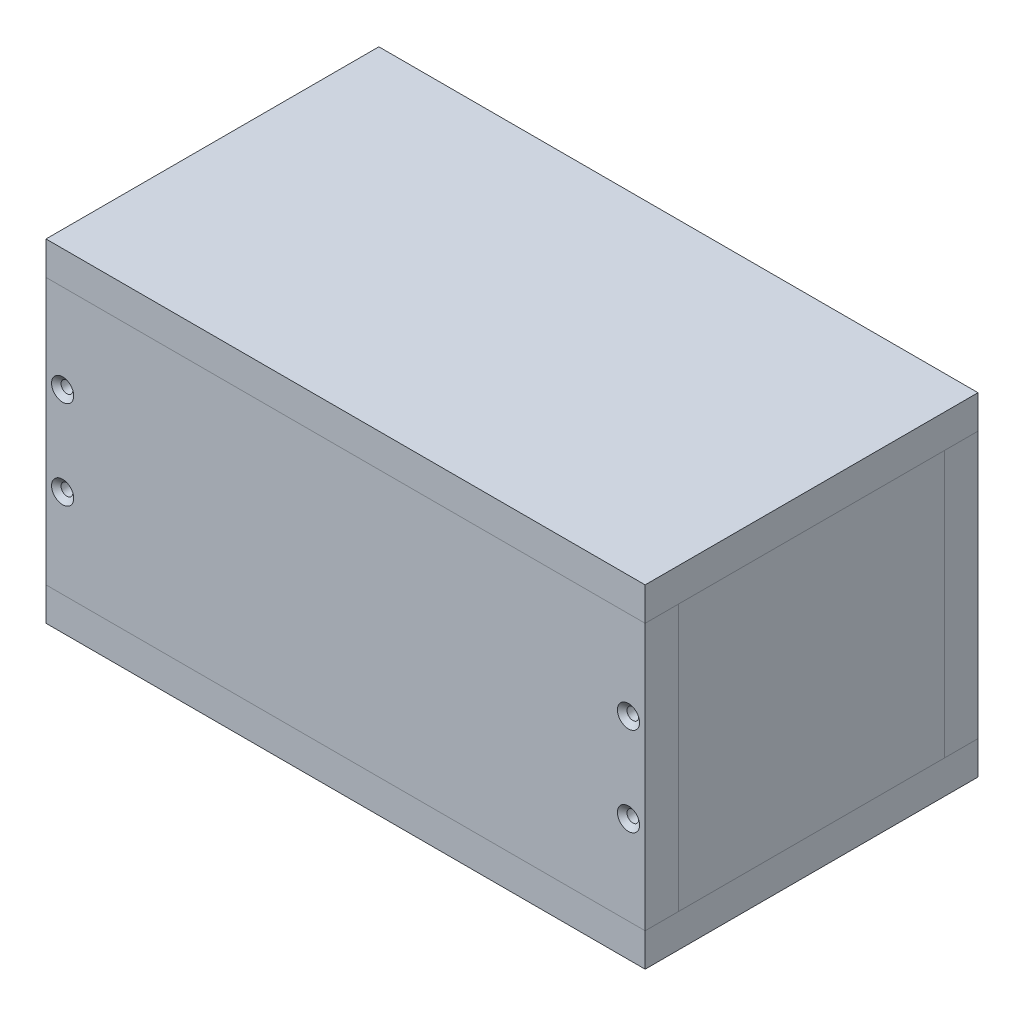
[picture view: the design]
ISO-10303-21;
HEADER;
FILE_DESCRIPTION(('STEP AP214'),'2;1');
FILE_NAME('part.step','',(''),(''),'','','');
FILE_SCHEMA(('AUTOMOTIVE_DESIGN { 1 0 10303 214 1 1 1 1 }'));
ENDSEC;
DATA;
#1=APPLICATION_CONTEXT('core data for automotive mechanical design processes');
#2=APPLICATION_PROTOCOL_DEFINITION('international standard','automotive_design',2000,#1);
#3=PRODUCT_CONTEXT('',#1,'mechanical');
#4=PRODUCT('Part','Part','',(#3));
#5=PRODUCT_RELATED_PRODUCT_CATEGORY('part','',(#4));
#6=PRODUCT_DEFINITION_FORMATION('','',#4);
#7=PRODUCT_DEFINITION_CONTEXT('part definition',#1,'design');
#8=PRODUCT_DEFINITION('design','',#6,#7);
#9=PRODUCT_DEFINITION_SHAPE('','',#8);
#10=(LENGTH_UNIT() NAMED_UNIT(*) SI_UNIT(.MILLI.,.METRE.));
#11=(NAMED_UNIT(*) PLANE_ANGLE_UNIT() SI_UNIT($,.RADIAN.));
#12=(NAMED_UNIT(*) SI_UNIT($,.STERADIAN.) SOLID_ANGLE_UNIT());
#13=UNCERTAINTY_MEASURE_WITH_UNIT(LENGTH_MEASURE(1.E-05),#10,'distance_accuracy_value','');
#14=(GEOMETRIC_REPRESENTATION_CONTEXT(3) GLOBAL_UNCERTAINTY_ASSIGNED_CONTEXT((#13)) GLOBAL_UNIT_ASSIGNED_CONTEXT((#10,
#11,#12)) REPRESENTATION_CONTEXT('',''));
#15=CARTESIAN_POINT('',(0.,0.,0.));
#16=DIRECTION('',(0.,0.,1.));
#17=DIRECTION('',(1.,0.,0.));
#18=AXIS2_PLACEMENT_3D('',#15,#16,#17);
#19=CARTESIAN_POINT('',(114.3,114.3,63.5));
#20=DIRECTION('',(-1.,0.,0.));
#21=DIRECTION('',(0.,0.,1.));
#22=AXIS2_PLACEMENT_3D('',#19,#20,#21);
#23=PLANE('',#22);
#24=DIRECTION('',(0.,0.,-1.));
#25=VECTOR('',#24,1.);
#26=CARTESIAN_POINT('',(114.3,101.6,63.5));
#27=LINE('',#26,#25);
#28=CARTESIAN_POINT('',(114.3,101.6,63.5));
#29=VERTEX_POINT('',#28);
#30=CARTESIAN_POINT('',(114.3,101.6,-63.5));
#31=VERTEX_POINT('',#30);
#32=EDGE_CURVE('E108',#29,#31,#27,.T.);
#33=ORIENTED_EDGE('',*,*,#32,.T.);
#34=DIRECTION('',(0.,-1.,0.));
#35=VECTOR('',#34,1.);
#36=CARTESIAN_POINT('',(114.3,114.3,-63.5));
#37=LINE('',#36,#35);
#38=CARTESIAN_POINT('',(114.3,114.3,-63.5));
#39=VERTEX_POINT('',#38);
#40=EDGE_CURVE('E12',#39,#31,#37,.T.);
#41=ORIENTED_EDGE('',*,*,#40,.F.);
#42=DIRECTION('',(0.,0.,-1.));
#43=VECTOR('',#42,1.);
#44=CARTESIAN_POINT('',(114.3,114.3,63.5));
#45=LINE('',#44,#43);
#46=CARTESIAN_POINT('',(114.3,114.3,63.5));
#47=VERTEX_POINT('',#46);
#48=EDGE_CURVE('E96',#47,#39,#45,.T.);
#49=ORIENTED_EDGE('',*,*,#48,.F.);
#50=DIRECTION('',(0.,-1.,0.));
#51=VECTOR('',#50,1.);
#52=CARTESIAN_POINT('',(114.3,114.3,63.5));
#53=LINE('',#52,#51);
#54=EDGE_CURVE('E104',#47,#29,#53,.T.);
#55=ORIENTED_EDGE('',*,*,#54,.T.);
#56=EDGE_LOOP('',(#33,#41,#49,#55));
#57=FACE_BOUND('',#56,.T.);
#58=ADVANCED_FACE('F45',(#57),#23,.F.);
#59=CARTESIAN_POINT('',(114.3,114.3,-63.5));
#60=DIRECTION('',(0.,0.,1.));
#61=DIRECTION('',(1.,0.,0.));
#62=AXIS2_PLACEMENT_3D('',#59,#60,#61);
#63=PLANE('',#62);
#64=DIRECTION('',(-1.,0.,0.));
#65=VECTOR('',#64,1.);
#66=CARTESIAN_POINT('',(114.3,101.6,-63.5));
#67=LINE('',#66,#65);
#68=CARTESIAN_POINT('',(-114.3,101.6,-63.5));
#69=VERTEX_POINT('',#68);
#70=EDGE_CURVE('E100',#31,#69,#67,.T.);
#71=ORIENTED_EDGE('',*,*,#70,.T.);
#72=DIRECTION('',(0.,-1.,0.));
#73=VECTOR('',#72,1.);
#74=CARTESIAN_POINT('',(-114.3,114.3,-63.5));
#75=LINE('',#74,#73);
#76=CARTESIAN_POINT('',(-114.3,114.3,-63.5));
#77=VERTEX_POINT('',#76);
#78=EDGE_CURVE('E53',#77,#69,#75,.T.);
#79=ORIENTED_EDGE('',*,*,#78,.F.);
#80=DIRECTION('',(-1.,0.,0.));
#81=VECTOR('',#80,1.);
#82=CARTESIAN_POINT('',(114.3,114.3,-63.5));
#83=LINE('',#82,#81);
#84=EDGE_CURVE('E91',#39,#77,#83,.T.);
#85=ORIENTED_EDGE('',*,*,#84,.F.);
#86=ORIENTED_EDGE('',*,*,#40,.T.);
#87=EDGE_LOOP('',(#71,#79,#85,#86));
#88=FACE_BOUND('',#87,.T.);
#89=ADVANCED_FACE('F99',(#88),#63,.F.);
#90=CARTESIAN_POINT('',(-114.3,114.3,63.5));
#91=DIRECTION('',(1.,0.,0.));
#92=DIRECTION('',(0.,0.,-1.));
#93=AXIS2_PLACEMENT_3D('',#90,#91,#92);
#94=PLANE('',#93);
#95=DIRECTION('',(0.,0.,1.));
#96=VECTOR('',#95,1.);
#97=CARTESIAN_POINT('',(-114.3,101.6,63.5));
#98=LINE('',#97,#96);
#99=CARTESIAN_POINT('',(-114.3,101.6,63.5));
#100=VERTEX_POINT('',#99);
#101=EDGE_CURVE('E78',#69,#100,#98,.T.);
#102=ORIENTED_EDGE('',*,*,#101,.T.);
#103=DIRECTION('',(0.,-1.,0.));
#104=VECTOR('',#103,1.);
#105=CARTESIAN_POINT('',(-114.3,114.3,63.5));
#106=LINE('',#105,#104);
#107=CARTESIAN_POINT('',(-114.3,114.3,63.5));
#108=VERTEX_POINT('',#107);
#109=EDGE_CURVE('E101',#108,#100,#106,.T.);
#110=ORIENTED_EDGE('',*,*,#109,.F.);
#111=DIRECTION('',(0.,0.,1.));
#112=VECTOR('',#111,1.);
#113=CARTESIAN_POINT('',(-114.3,114.3,63.5));
#114=LINE('',#113,#112);
#115=EDGE_CURVE('E94',#77,#108,#114,.T.);
#116=ORIENTED_EDGE('',*,*,#115,.F.);
#117=ORIENTED_EDGE('',*,*,#78,.T.);
#118=EDGE_LOOP('',(#102,#110,#116,#117));
#119=FACE_BOUND('',#118,.T.);
#120=ADVANCED_FACE('F102',(#119),#94,.F.);
#121=CARTESIAN_POINT('',(114.3,114.3,63.5));
#122=DIRECTION('',(0.,0.,-1.));
#123=DIRECTION('',(-1.,0.,0.));
#124=AXIS2_PLACEMENT_3D('',#121,#122,#123);
#125=PLANE('',#124);
#126=DIRECTION('',(1.,0.,0.));
#127=VECTOR('',#126,1.);
#128=CARTESIAN_POINT('',(114.3,101.6,63.5));
#129=LINE('',#128,#127);
#130=EDGE_CURVE('E84',#100,#29,#129,.T.);
#131=ORIENTED_EDGE('',*,*,#130,.T.);
#132=ORIENTED_EDGE('',*,*,#54,.F.);
#133=DIRECTION('',(1.,0.,0.));
#134=VECTOR('',#133,1.);
#135=CARTESIAN_POINT('',(114.3,114.3,63.5));
#136=LINE('',#135,#134);
#137=EDGE_CURVE('E61',#108,#47,#136,.T.);
#138=ORIENTED_EDGE('',*,*,#137,.F.);
#139=ORIENTED_EDGE('',*,*,#109,.T.);
#140=EDGE_LOOP('',(#131,#132,#138,#139));
#141=FACE_BOUND('',#140,.T.);
#142=ADVANCED_FACE('F115',(#141),#125,.F.);
#143=CARTESIAN_POINT('',(0.,114.3,0.));
#144=DIRECTION('',(0.,1.,0.));
#145=DIRECTION('',(0.,0.,1.));
#146=AXIS2_PLACEMENT_3D('',#143,#144,#145);
#147=PLANE('',#146);
#148=ORIENTED_EDGE('',*,*,#48,.T.);
#149=ORIENTED_EDGE('',*,*,#84,.T.);
#150=ORIENTED_EDGE('',*,*,#115,.T.);
#151=ORIENTED_EDGE('',*,*,#137,.T.);
#152=EDGE_LOOP('',(#148,#149,#150,#151));
#153=FACE_BOUND('',#152,.T.);
#154=ADVANCED_FACE('F92',(#153),#147,.T.);
#155=CARTESIAN_POINT('',(0.,101.6,0.));
#156=DIRECTION('',(0.,1.,0.));
#157=DIRECTION('',(0.,0.,1.));
#158=AXIS2_PLACEMENT_3D('',#155,#156,#157);
#159=PLANE('',#158);
#160=ORIENTED_EDGE('',*,*,#32,.F.);
#161=ORIENTED_EDGE('',*,*,#130,.F.);
#162=ORIENTED_EDGE('',*,*,#101,.F.);
#163=ORIENTED_EDGE('',*,*,#70,.F.);
#164=EDGE_LOOP('',(#160,#161,#162,#163));
#165=FACE_BOUND('',#164,.T.);
#166=ADVANCED_FACE('F118',(#165),#159,.F.);
#167=CLOSED_SHELL('',(#58,#89,#120,#142,#154,#166));
#168=MANIFOLD_SOLID_BREP('B2_NOT_SHOWN',#167);
#169=CARTESIAN_POINT('',(114.3,-12.7,-63.5));
#170=DIRECTION('',(1.,0.,0.));
#171=DIRECTION('',(0.,0.,-1.));
#172=AXIS2_PLACEMENT_3D('',#169,#170,#171);
#173=PLANE('',#172);
#174=DIRECTION('',(0.,0.,-1.));
#175=VECTOR('',#174,1.);
#176=CARTESIAN_POINT('',(114.3,0.,-63.5));
#177=LINE('',#176,#175);
#178=CARTESIAN_POINT('',(114.3,0.,63.4999999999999));
#179=VERTEX_POINT('',#178);
#180=CARTESIAN_POINT('',(114.3,0.,-63.5));
#181=VERTEX_POINT('',#180);
#182=EDGE_CURVE('E245',#179,#181,#177,.T.);
#183=ORIENTED_EDGE('',*,*,#182,.F.);
#184=DIRECTION('',(0.,1.,0.));
#185=VECTOR('',#184,1.);
#186=CARTESIAN_POINT('',(114.3,-12.7,63.4999999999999));
#187=LINE('',#186,#185);
#188=CARTESIAN_POINT('',(114.3,-12.7,63.4999999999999));
#189=VERTEX_POINT('',#188);
#190=EDGE_CURVE('E43',#189,#179,#187,.T.);
#191=ORIENTED_EDGE('',*,*,#190,.F.);
#192=DIRECTION('',(0.,0.,-1.));
#193=VECTOR('',#192,1.);
#194=CARTESIAN_POINT('',(114.3,-12.7,-63.5));
#195=LINE('',#194,#193);
#196=CARTESIAN_POINT('',(114.3,-12.7,-63.5));
#197=VERTEX_POINT('',#196);
#198=EDGE_CURVE('E238',#189,#197,#195,.T.);
#199=ORIENTED_EDGE('',*,*,#198,.T.);
#200=DIRECTION('',(0.,1.,0.));
#201=VECTOR('',#200,1.);
#202=CARTESIAN_POINT('',(114.3,-12.7,-63.5));
#203=LINE('',#202,#201);
#204=EDGE_CURVE('E221',#197,#181,#203,.T.);
#205=ORIENTED_EDGE('',*,*,#204,.T.);
#206=EDGE_LOOP('',(#183,#191,#199,#205));
#207=FACE_BOUND('',#206,.T.);
#208=ADVANCED_FACE('F178',(#207),#173,.T.);
#209=CARTESIAN_POINT('',(114.3,-12.7,63.4999999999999));
#210=DIRECTION('',(0.,0.,1.));
#211=DIRECTION('',(1.,0.,0.));
#212=AXIS2_PLACEMENT_3D('',#209,#210,#211);
#213=PLANE('',#212);
#214=DIRECTION('',(1.,0.,0.));
#215=VECTOR('',#214,1.);
#216=CARTESIAN_POINT('',(114.3,0.,63.4999999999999));
#217=LINE('',#216,#215);
#218=CARTESIAN_POINT('',(-114.3,0.,63.5));
#219=VERTEX_POINT('',#218);
#220=EDGE_CURVE('E240',#219,#179,#217,.T.);
#221=ORIENTED_EDGE('',*,*,#220,.F.);
#222=DIRECTION('',(0.,1.,0.));
#223=VECTOR('',#222,1.);
#224=CARTESIAN_POINT('',(-114.3,-12.7,63.5));
#225=LINE('',#224,#223);
#226=CARTESIAN_POINT('',(-114.3,-12.7,63.5));
#227=VERTEX_POINT('',#226);
#228=EDGE_CURVE('E187',#227,#219,#225,.T.);
#229=ORIENTED_EDGE('',*,*,#228,.F.);
#230=DIRECTION('',(1.,0.,0.));
#231=VECTOR('',#230,1.);
#232=CARTESIAN_POINT('',(114.3,-12.7,63.4999999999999));
#233=LINE('',#232,#231);
#234=EDGE_CURVE('E235',#227,#189,#233,.T.);
#235=ORIENTED_EDGE('',*,*,#234,.T.);
#236=ORIENTED_EDGE('',*,*,#190,.T.);
#237=EDGE_LOOP('',(#221,#229,#235,#236));
#238=FACE_BOUND('',#237,.T.);
#239=ADVANCED_FACE('F310',(#238),#213,.T.);
#240=CARTESIAN_POINT('',(-114.3,-12.7,-63.5));
#241=DIRECTION('',(-1.,0.,0.));
#242=DIRECTION('',(0.,0.,1.));
#243=AXIS2_PLACEMENT_3D('',#240,#241,#242);
#244=PLANE('',#243);
#245=DIRECTION('',(0.,0.,1.));
#246=VECTOR('',#245,1.);
#247=CARTESIAN_POINT('',(-114.3,0.,-63.5));
#248=LINE('',#247,#246);
#249=CARTESIAN_POINT('',(-114.3,0.,-63.5));
#250=VERTEX_POINT('',#249);
#251=EDGE_CURVE('E229',#250,#219,#248,.T.);
#252=ORIENTED_EDGE('',*,*,#251,.F.);
#253=DIRECTION('',(0.,1.,0.));
#254=VECTOR('',#253,1.);
#255=CARTESIAN_POINT('',(-114.3,-12.7,-63.5));
#256=LINE('',#255,#254);
#257=CARTESIAN_POINT('',(-114.3,-12.7,-63.5));
#258=VERTEX_POINT('',#257);
#259=EDGE_CURVE('E224',#258,#250,#256,.T.);
#260=ORIENTED_EDGE('',*,*,#259,.F.);
#261=DIRECTION('',(0.,0.,1.));
#262=VECTOR('',#261,1.);
#263=CARTESIAN_POINT('',(-114.3,-12.7,-63.5));
#264=LINE('',#263,#262);
#265=EDGE_CURVE('E227',#258,#227,#264,.T.);
#266=ORIENTED_EDGE('',*,*,#265,.T.);
#267=ORIENTED_EDGE('',*,*,#228,.T.);
#268=EDGE_LOOP('',(#252,#260,#266,#267));
#269=FACE_BOUND('',#268,.T.);
#270=ADVANCED_FACE('F226',(#269),#244,.T.);
#271=CARTESIAN_POINT('',(114.3,-12.7,-63.5));
#272=DIRECTION('',(0.,0.,-1.));
#273=DIRECTION('',(-1.,0.,0.));
#274=AXIS2_PLACEMENT_3D('',#271,#272,#273);
#275=PLANE('',#274);
#276=DIRECTION('',(-1.,0.,0.));
#277=VECTOR('',#276,1.);
#278=CARTESIAN_POINT('',(114.3,0.,-63.5));
#279=LINE('',#278,#277);
#280=EDGE_CURVE('E248',#181,#250,#279,.T.);
#281=ORIENTED_EDGE('',*,*,#280,.F.);
#282=ORIENTED_EDGE('',*,*,#204,.F.);
#283=DIRECTION('',(-1.,0.,0.));
#284=VECTOR('',#283,1.);
#285=CARTESIAN_POINT('',(114.3,-12.7,-63.5));
#286=LINE('',#285,#284);
#287=EDGE_CURVE('E234',#197,#258,#286,.T.);
#288=ORIENTED_EDGE('',*,*,#287,.T.);
#289=ORIENTED_EDGE('',*,*,#259,.T.);
#290=EDGE_LOOP('',(#281,#282,#288,#289));
#291=FACE_BOUND('',#290,.T.);
#292=ADVANCED_FACE('F237',(#291),#275,.T.);
#293=CARTESIAN_POINT('',(0.,-12.7,0.));
#294=DIRECTION('',(0.,-1.,0.));
#295=DIRECTION('',(0.,0.,-1.));
#296=AXIS2_PLACEMENT_3D('',#293,#294,#295);
#297=PLANE('',#296);
#298=CARTESIAN_POINT('',(57.1500000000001,-12.7,-57.15));
#299=DIRECTION('',(0.,-1.,0.));
#300=DIRECTION('',(0.,0.,-1.));
#301=AXIS2_PLACEMENT_3D('',#298,#299,#300);
#302=CIRCLE('',#301,4.2164);
#303=CARTESIAN_POINT('',(57.1500000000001,-12.7,-61.3664));
#304=VERTEX_POINT('',#303);
#305=EDGE_CURVE('E416',#304,#304,#302,.T.);
#306=ORIENTED_EDGE('',*,*,#305,.F.);
#307=EDGE_LOOP('',(#306));
#308=FACE_BOUND('',#307,.T.);
#309=CARTESIAN_POINT('',(-57.15,-12.7,-57.15));
#310=DIRECTION('',(0.,-1.,0.));
#311=DIRECTION('',(0.,0.,-1.));
#312=AXIS2_PLACEMENT_3D('',#309,#310,#311);
#313=CIRCLE('',#312,4.2164);
#314=CARTESIAN_POINT('',(-57.15,-12.7,-61.3664));
#315=VERTEX_POINT('',#314);
#316=EDGE_CURVE('E272',#315,#315,#313,.T.);
#317=ORIENTED_EDGE('',*,*,#316,.F.);
#318=EDGE_LOOP('',(#317));
#319=FACE_BOUND('',#318,.T.);
#320=CARTESIAN_POINT('',(-57.15,-12.7,57.15));
#321=DIRECTION('',(0.,-1.,0.));
#322=DIRECTION('',(0.,0.,-1.));
#323=AXIS2_PLACEMENT_3D('',#320,#321,#322);
#324=CIRCLE('',#323,4.2164);
#325=CARTESIAN_POINT('',(-57.15,-12.7,52.9336));
#326=VERTEX_POINT('',#325);
#327=EDGE_CURVE('E265',#326,#326,#324,.T.);
#328=ORIENTED_EDGE('',*,*,#327,.F.);
#329=EDGE_LOOP('',(#328));
#330=FACE_BOUND('',#329,.T.);
#331=CARTESIAN_POINT('',(57.1500000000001,-12.7,57.15));
#332=DIRECTION('',(0.,-1.,0.));
#333=DIRECTION('',(0.,0.,-1.));
#334=AXIS2_PLACEMENT_3D('',#331,#332,#333);
#335=CIRCLE('',#334,4.2164);
#336=CARTESIAN_POINT('',(57.1500000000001,-12.7,52.9336));
#337=VERTEX_POINT('',#336);
#338=EDGE_CURVE('E261',#337,#337,#335,.T.);
#339=ORIENTED_EDGE('',*,*,#338,.F.);
#340=EDGE_LOOP('',(#339));
#341=FACE_BOUND('',#340,.T.);
#342=ORIENTED_EDGE('',*,*,#198,.F.);
#343=ORIENTED_EDGE('',*,*,#234,.F.);
#344=ORIENTED_EDGE('',*,*,#265,.F.);
#345=ORIENTED_EDGE('',*,*,#287,.F.);
#346=EDGE_LOOP('',(#342,#343,#344,#345));
#347=FACE_BOUND('',#346,.T.);
#348=ADVANCED_FACE('F233',(#308,#319,#330,#341,#347),#297,.T.);
#349=CARTESIAN_POINT('',(0.,0.,0.));
#350=DIRECTION('',(0.,-1.,0.));
#351=DIRECTION('',(0.,0.,-1.));
#352=AXIS2_PLACEMENT_3D('',#349,#350,#351);
#353=PLANE('',#352);
#354=CARTESIAN_POINT('',(57.1500000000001,0.,-57.15));
#355=DIRECTION('',(0.,-1.,0.));
#356=DIRECTION('',(0.,0.,-1.));
#357=AXIS2_PLACEMENT_3D('',#354,#355,#356);
#358=CIRCLE('',#357,2.24789999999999);
#359=CARTESIAN_POINT('',(57.1500000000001,0.,-59.3979));
#360=VERTEX_POINT('',#359);
#361=EDGE_CURVE('E181',#360,#360,#358,.T.);
#362=ORIENTED_EDGE('',*,*,#361,.T.);
#363=EDGE_LOOP('',(#362));
#364=FACE_BOUND('',#363,.T.);
#365=CARTESIAN_POINT('',(-57.15,0.,-57.15));
#366=DIRECTION('',(0.,-1.,0.));
#367=DIRECTION('',(0.,0.,-1.));
#368=AXIS2_PLACEMENT_3D('',#365,#366,#367);
#369=CIRCLE('',#368,2.24789999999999);
#370=CARTESIAN_POINT('',(-57.15,0.,-59.3979));
#371=VERTEX_POINT('',#370);
#372=EDGE_CURVE('E263',#371,#371,#369,.T.);
#373=ORIENTED_EDGE('',*,*,#372,.T.);
#374=EDGE_LOOP('',(#373));
#375=FACE_BOUND('',#374,.T.);
#376=CARTESIAN_POINT('',(-57.15,0.,57.15));
#377=DIRECTION('',(0.,-1.,0.));
#378=DIRECTION('',(0.,0.,-1.));
#379=AXIS2_PLACEMENT_3D('',#376,#377,#378);
#380=CIRCLE('',#379,2.24789999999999);
#381=CARTESIAN_POINT('',(-57.15,0.,54.9021));
#382=VERTEX_POINT('',#381);
#383=EDGE_CURVE('E259',#382,#382,#380,.T.);
#384=ORIENTED_EDGE('',*,*,#383,.T.);
#385=EDGE_LOOP('',(#384));
#386=FACE_BOUND('',#385,.T.);
#387=CARTESIAN_POINT('',(57.1500000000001,0.,57.15));
#388=DIRECTION('',(0.,-1.,0.));
#389=DIRECTION('',(0.,0.,-1.));
#390=AXIS2_PLACEMENT_3D('',#387,#388,#389);
#391=CIRCLE('',#390,2.24789999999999);
#392=CARTESIAN_POINT('',(57.1500000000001,0.,54.9021));
#393=VERTEX_POINT('',#392);
#394=EDGE_CURVE('E249',#393,#393,#391,.T.);
#395=ORIENTED_EDGE('',*,*,#394,.T.);
#396=EDGE_LOOP('',(#395));
#397=FACE_BOUND('',#396,.T.);
#398=ORIENTED_EDGE('',*,*,#182,.T.);
#399=ORIENTED_EDGE('',*,*,#280,.T.);
#400=ORIENTED_EDGE('',*,*,#251,.T.);
#401=ORIENTED_EDGE('',*,*,#220,.T.);
#402=EDGE_LOOP('',(#398,#399,#400,#401));
#403=FACE_BOUND('',#402,.T.);
#404=ADVANCED_FACE('F297',(#364,#375,#386,#397,#403),#353,.F.);
#405=CARTESIAN_POINT('',(57.1500000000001,-12.7,57.15));
#406=DIRECTION('',(0.,-1.,0.));
#407=DIRECTION('',(0.,0.,-1.));
#408=AXIS2_PLACEMENT_3D('',#405,#406,#407);
#409=CYLINDRICAL_SURFACE('',#408,2.24789999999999);
#410=CARTESIAN_POINT('',(57.1500000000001,-11.0482323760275,57.15));
#411=DIRECTION('',(0.,-1.,0.));
#412=DIRECTION('',(0.,0.,-1.));
#413=AXIS2_PLACEMENT_3D('',#410,#411,#412);
#414=CIRCLE('',#413,2.2479);
#415=CARTESIAN_POINT('',(57.1500000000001,-11.0482323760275,54.9021));
#416=VERTEX_POINT('',#415);
#417=EDGE_CURVE('E258',#416,#416,#414,.T.);
#418=ORIENTED_EDGE('',*,*,#417,.T.);
#419=EDGE_LOOP('',(#418));
#420=FACE_BOUND('',#419,.T.);
#421=ORIENTED_EDGE('',*,*,#394,.F.);
#422=EDGE_LOOP('',(#421));
#423=FACE_BOUND('',#422,.T.);
#424=ADVANCED_FACE('F286',(#420,#423),#409,.F.);
#425=CARTESIAN_POINT('',(57.1500000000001,-12.7,57.15));
#426=DIRECTION('',(0.,-1.,0.));
#427=DIRECTION('',(0.,0.,-1.));
#428=AXIS2_PLACEMENT_3D('',#425,#426,#427);
#429=CONICAL_SURFACE('',#428,4.2164,0.872664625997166);
#430=ORIENTED_EDGE('',*,*,#417,.F.);
#431=EDGE_LOOP('',(#430));
#432=FACE_BOUND('',#431,.T.);
#433=ORIENTED_EDGE('',*,*,#338,.T.);
#434=EDGE_LOOP('',(#433));
#435=FACE_BOUND('',#434,.T.);
#436=ADVANCED_FACE('F289',(#432,#435),#429,.F.);
#437=CARTESIAN_POINT('',(-57.15,-12.7,57.15));
#438=DIRECTION('',(0.,-1.,0.));
#439=DIRECTION('',(0.,0.,-1.));
#440=AXIS2_PLACEMENT_3D('',#437,#438,#439);
#441=CYLINDRICAL_SURFACE('',#440,2.24789999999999);
#442=CARTESIAN_POINT('',(-57.15,-11.0482323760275,57.15));
#443=DIRECTION('',(0.,-1.,0.));
#444=DIRECTION('',(0.,0.,-1.));
#445=AXIS2_PLACEMENT_3D('',#442,#443,#444);
#446=CIRCLE('',#445,2.2479);
#447=CARTESIAN_POINT('',(-57.15,-11.0482323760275,54.9021));
#448=VERTEX_POINT('',#447);
#449=EDGE_CURVE('E262',#448,#448,#446,.T.);
#450=ORIENTED_EDGE('',*,*,#449,.T.);
#451=EDGE_LOOP('',(#450));
#452=FACE_BOUND('',#451,.T.);
#453=ORIENTED_EDGE('',*,*,#383,.F.);
#454=EDGE_LOOP('',(#453));
#455=FACE_BOUND('',#454,.T.);
#456=ADVANCED_FACE('F292',(#452,#455),#441,.F.);
#457=CARTESIAN_POINT('',(-57.15,-12.7,57.15));
#458=DIRECTION('',(0.,-1.,0.));
#459=DIRECTION('',(0.,0.,-1.));
#460=AXIS2_PLACEMENT_3D('',#457,#458,#459);
#461=CONICAL_SURFACE('',#460,4.2164,0.872664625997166);
#462=ORIENTED_EDGE('',*,*,#449,.F.);
#463=EDGE_LOOP('',(#462));
#464=FACE_BOUND('',#463,.T.);
#465=ORIENTED_EDGE('',*,*,#327,.T.);
#466=EDGE_LOOP('',(#465));
#467=FACE_BOUND('',#466,.T.);
#468=ADVANCED_FACE('F358',(#464,#467),#461,.F.);
#469=CARTESIAN_POINT('',(-57.15,-12.7,-57.15));
#470=DIRECTION('',(0.,-1.,0.));
#471=DIRECTION('',(0.,0.,-1.));
#472=AXIS2_PLACEMENT_3D('',#469,#470,#471);
#473=CYLINDRICAL_SURFACE('',#472,2.24789999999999);
#474=CARTESIAN_POINT('',(-57.15,-11.0482323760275,-57.15));
#475=DIRECTION('',(0.,-1.,0.));
#476=DIRECTION('',(0.,0.,-1.));
#477=AXIS2_PLACEMENT_3D('',#474,#475,#476);
#478=CIRCLE('',#477,2.2479);
#479=CARTESIAN_POINT('',(-57.15,-11.0482323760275,-59.3979));
#480=VERTEX_POINT('',#479);
#481=EDGE_CURVE('E266',#480,#480,#478,.T.);
#482=ORIENTED_EDGE('',*,*,#481,.T.);
#483=EDGE_LOOP('',(#482));
#484=FACE_BOUND('',#483,.T.);
#485=ORIENTED_EDGE('',*,*,#372,.F.);
#486=EDGE_LOOP('',(#485));
#487=FACE_BOUND('',#486,.T.);
#488=ADVANCED_FACE('F368',(#484,#487),#473,.F.);
#489=CARTESIAN_POINT('',(-57.15,-12.7,-57.15));
#490=DIRECTION('',(0.,-1.,0.));
#491=DIRECTION('',(0.,0.,-1.));
#492=AXIS2_PLACEMENT_3D('',#489,#490,#491);
#493=CONICAL_SURFACE('',#492,4.2164,0.872664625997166);
#494=ORIENTED_EDGE('',*,*,#481,.F.);
#495=EDGE_LOOP('',(#494));
#496=FACE_BOUND('',#495,.T.);
#497=ORIENTED_EDGE('',*,*,#316,.T.);
#498=EDGE_LOOP('',(#497));
#499=FACE_BOUND('',#498,.T.);
#500=ADVANCED_FACE('F378',(#496,#499),#493,.F.);
#501=CARTESIAN_POINT('',(57.1500000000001,-12.7,-57.15));
#502=DIRECTION('',(0.,-1.,0.));
#503=DIRECTION('',(0.,0.,-1.));
#504=AXIS2_PLACEMENT_3D('',#501,#502,#503);
#505=CYLINDRICAL_SURFACE('',#504,2.24789999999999);
#506=CARTESIAN_POINT('',(57.1500000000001,-11.0482323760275,-57.15));
#507=DIRECTION('',(0.,-1.,0.));
#508=DIRECTION('',(0.,0.,-1.));
#509=AXIS2_PLACEMENT_3D('',#506,#507,#508);
#510=CIRCLE('',#509,2.2479);
#511=CARTESIAN_POINT('',(57.1500000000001,-11.0482323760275,-59.3979));
#512=VERTEX_POINT('',#511);
#513=EDGE_CURVE('E414',#512,#512,#510,.T.);
#514=ORIENTED_EDGE('',*,*,#513,.T.);
#515=EDGE_LOOP('',(#514));
#516=FACE_BOUND('',#515,.T.);
#517=ORIENTED_EDGE('',*,*,#361,.F.);
#518=EDGE_LOOP('',(#517));
#519=FACE_BOUND('',#518,.T.);
#520=ADVANCED_FACE('F387',(#516,#519),#505,.F.);
#521=CARTESIAN_POINT('',(57.1500000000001,-12.7,-57.15));
#522=DIRECTION('',(0.,-1.,0.));
#523=DIRECTION('',(0.,0.,-1.));
#524=AXIS2_PLACEMENT_3D('',#521,#522,#523);
#525=CONICAL_SURFACE('',#524,4.2164,0.872664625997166);
#526=ORIENTED_EDGE('',*,*,#513,.F.);
#527=EDGE_LOOP('',(#526));
#528=FACE_BOUND('',#527,.T.);
#529=ORIENTED_EDGE('',*,*,#305,.T.);
#530=EDGE_LOOP('',(#529));
#531=FACE_BOUND('',#530,.T.);
#532=ADVANCED_FACE('F397',(#528,#531),#525,.F.);
#533=CLOSED_SHELL('',(#208,#239,#270,#292,#348,#404,#424,#436,#456,#468,#488,#500,#520,#532));
#534=MANIFOLD_SOLID_BREP('B6',#533);
#535=CARTESIAN_POINT('',(-101.6,101.6,50.8));
#536=DIRECTION('',(-1.,0.,0.));
#537=DIRECTION('',(0.,0.,1.));
#538=AXIS2_PLACEMENT_3D('',#535,#536,#537);
#539=PLANE('',#538);
#540=DIRECTION('',(0.,0.,-1.));
#541=VECTOR('',#540,1.);
#542=CARTESIAN_POINT('',(-101.6,0.,50.8));
#543=LINE('',#542,#541);
#544=CARTESIAN_POINT('',(-101.6,0.,50.8));
#545=VERTEX_POINT('',#544);
#546=CARTESIAN_POINT('',(-101.6,0.,-50.8));
#547=VERTEX_POINT('',#546);
#548=EDGE_CURVE('E551',#545,#547,#543,.T.);
#549=ORIENTED_EDGE('',*,*,#548,.T.);
#550=DIRECTION('',(0.,-1.,0.));
#551=VECTOR('',#550,1.);
#552=CARTESIAN_POINT('',(-101.6,101.6,-50.8));
#553=LINE('',#552,#551);
#554=CARTESIAN_POINT('',(-101.6,101.6,-50.8));
#555=VERTEX_POINT('',#554);
#556=EDGE_CURVE('E176',#555,#547,#553,.T.);
#557=ORIENTED_EDGE('',*,*,#556,.F.);
#558=DIRECTION('',(0.,0.,-1.));
#559=VECTOR('',#558,1.);
#560=CARTESIAN_POINT('',(-101.6,101.6,50.8));
#561=LINE('',#560,#559);
#562=CARTESIAN_POINT('',(-101.6,101.6,50.8));
#563=VERTEX_POINT('',#562);
#564=EDGE_CURVE('E544',#563,#555,#561,.T.);
#565=ORIENTED_EDGE('',*,*,#564,.F.);
#566=DIRECTION('',(0.,-1.,0.));
#567=VECTOR('',#566,1.);
#568=CARTESIAN_POINT('',(-101.6,101.6,50.8));
#569=LINE('',#568,#567);
#570=EDGE_CURVE('E550',#563,#545,#569,.T.);
#571=ORIENTED_EDGE('',*,*,#570,.T.);
#572=EDGE_LOOP('',(#549,#557,#565,#571));
#573=FACE_BOUND('',#572,.T.);
#574=ADVANCED_FACE('F455',(#573),#539,.F.);
#575=CARTESIAN_POINT('',(-101.6,101.6,-50.8));
#576=DIRECTION('',(0.,0.,1.));
#577=DIRECTION('',(1.,0.,0.));
#578=AXIS2_PLACEMENT_3D('',#575,#576,#577);
#579=PLANE('',#578);
#580=CARTESIAN_POINT('',(-107.95,33.8666666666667,-50.8));
#581=DIRECTION('',(0.,0.,-1.));
#582=DIRECTION('',(-1.,0.,0.));
#583=AXIS2_PLACEMENT_3D('',#580,#581,#582);
#584=CIRCLE('',#583,2.2479);
#585=CARTESIAN_POINT('',(-110.1979,33.8666666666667,-50.8));
#586=VERTEX_POINT('',#585);
#587=EDGE_CURVE('E527',#586,#586,#584,.T.);
#588=ORIENTED_EDGE('',*,*,#587,.F.);
#589=EDGE_LOOP('',(#588));
#590=FACE_BOUND('',#589,.T.);
#591=CARTESIAN_POINT('',(-107.95,67.7333333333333,-50.8));
#592=DIRECTION('',(0.,0.,-1.));
#593=DIRECTION('',(-1.,0.,0.));
#594=AXIS2_PLACEMENT_3D('',#591,#592,#593);
#595=CIRCLE('',#594,2.2479);
#596=CARTESIAN_POINT('',(-110.1979,67.7333333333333,-50.8));
#597=VERTEX_POINT('',#596);
#598=EDGE_CURVE('E526',#597,#597,#595,.T.);
#599=ORIENTED_EDGE('',*,*,#598,.F.);
#600=EDGE_LOOP('',(#599));
#601=FACE_BOUND('',#600,.T.);
#602=DIRECTION('',(-1.,0.,0.));
#603=VECTOR('',#602,1.);
#604=CARTESIAN_POINT('',(-101.6,0.,-50.8));
#605=LINE('',#604,#603);
#606=CARTESIAN_POINT('',(-114.3,0.,-50.8));
#607=VERTEX_POINT('',#606);
#608=EDGE_CURVE('E554',#547,#607,#605,.T.);
#609=ORIENTED_EDGE('',*,*,#608,.T.);
#610=DIRECTION('',(0.,-1.,0.));
#611=VECTOR('',#610,1.);
#612=CARTESIAN_POINT('',(-114.3,101.6,-50.8));
#613=LINE('',#612,#611);
#614=CARTESIAN_POINT('',(-114.3,101.6,-50.8));
#615=VERTEX_POINT('',#614);
#616=EDGE_CURVE('E464',#615,#607,#613,.T.);
#617=ORIENTED_EDGE('',*,*,#616,.F.);
#618=DIRECTION('',(-1.,0.,0.));
#619=VECTOR('',#618,1.);
#620=CARTESIAN_POINT('',(-101.6,101.6,-50.8));
#621=LINE('',#620,#619);
#622=EDGE_CURVE('E504',#555,#615,#621,.T.);
#623=ORIENTED_EDGE('',*,*,#622,.F.);
#624=ORIENTED_EDGE('',*,*,#556,.T.);
#625=EDGE_LOOP('',(#609,#617,#623,#624));
#626=FACE_BOUND('',#625,.T.);
#627=ADVANCED_FACE('F585',(#590,#601,#626),#579,.F.);
#628=CARTESIAN_POINT('',(-114.3,101.6,50.8));
#629=DIRECTION('',(1.,0.,0.));
#630=DIRECTION('',(0.,0.,-1.));
#631=AXIS2_PLACEMENT_3D('',#628,#629,#630);
#632=PLANE('',#631);
#633=DIRECTION('',(0.,0.,1.));
#634=VECTOR('',#633,1.);
#635=CARTESIAN_POINT('',(-114.3,0.,50.8));
#636=LINE('',#635,#634);
#637=CARTESIAN_POINT('',(-114.3,0.,50.8));
#638=VERTEX_POINT('',#637);
#639=EDGE_CURVE('E491',#607,#638,#636,.T.);
#640=ORIENTED_EDGE('',*,*,#639,.T.);
#641=DIRECTION('',(0.,-1.,0.));
#642=VECTOR('',#641,1.);
#643=CARTESIAN_POINT('',(-114.3,101.6,50.8));
#644=LINE('',#643,#642);
#645=CARTESIAN_POINT('',(-114.3,101.6,50.8));
#646=VERTEX_POINT('',#645);
#647=EDGE_CURVE('E559',#646,#638,#644,.T.);
#648=ORIENTED_EDGE('',*,*,#647,.F.);
#649=DIRECTION('',(0.,0.,1.));
#650=VECTOR('',#649,1.);
#651=CARTESIAN_POINT('',(-114.3,101.6,50.8));
#652=LINE('',#651,#650);
#653=EDGE_CURVE('E547',#615,#646,#652,.T.);
#654=ORIENTED_EDGE('',*,*,#653,.F.);
#655=ORIENTED_EDGE('',*,*,#616,.T.);
#656=EDGE_LOOP('',(#640,#648,#654,#655));
#657=FACE_BOUND('',#656,.T.);
#658=ADVANCED_FACE('F590',(#657),#632,.F.);
#659=CARTESIAN_POINT('',(-101.6,101.6,50.8));
#660=DIRECTION('',(0.,0.,-1.));
#661=DIRECTION('',(-1.,0.,0.));
#662=AXIS2_PLACEMENT_3D('',#659,#660,#661);
#663=PLANE('',#662);
#664=CARTESIAN_POINT('',(-107.95,67.7333333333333,50.8));
#665=DIRECTION('',(0.,0.,-1.));
#666=DIRECTION('',(-1.,0.,0.));
#667=AXIS2_PLACEMENT_3D('',#664,#665,#666);
#668=CIRCLE('',#667,2.2479);
#669=CARTESIAN_POINT('',(-110.1979,67.7333333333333,50.8));
#670=VERTEX_POINT('',#669);
#671=EDGE_CURVE('E458',#670,#670,#668,.T.);
#672=ORIENTED_EDGE('',*,*,#671,.T.);
#673=EDGE_LOOP('',(#672));
#674=FACE_BOUND('',#673,.T.);
#675=CARTESIAN_POINT('',(-107.95,33.8666666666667,50.8));
#676=DIRECTION('',(0.,0.,-1.));
#677=DIRECTION('',(-1.,0.,0.));
#678=AXIS2_PLACEMENT_3D('',#675,#676,#677);
#679=CIRCLE('',#678,2.2479);
#680=CARTESIAN_POINT('',(-110.1979,33.8666666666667,50.8));
#681=VERTEX_POINT('',#680);
#682=EDGE_CURVE('E543',#681,#681,#679,.T.);
#683=ORIENTED_EDGE('',*,*,#682,.T.);
#684=EDGE_LOOP('',(#683));
#685=FACE_BOUND('',#684,.T.);
#686=DIRECTION('',(1.,0.,0.));
#687=VECTOR('',#686,1.);
#688=CARTESIAN_POINT('',(-101.6,0.,50.8));
#689=LINE('',#688,#687);
#690=EDGE_CURVE('E497',#638,#545,#689,.T.);
#691=ORIENTED_EDGE('',*,*,#690,.T.);
#692=ORIENTED_EDGE('',*,*,#570,.F.);
#693=DIRECTION('',(1.,0.,0.));
#694=VECTOR('',#693,1.);
#695=CARTESIAN_POINT('',(-101.6,101.6,50.8));
#696=LINE('',#695,#694);
#697=EDGE_CURVE('E473',#646,#563,#696,.T.);
#698=ORIENTED_EDGE('',*,*,#697,.F.);
#699=ORIENTED_EDGE('',*,*,#647,.T.);
#700=EDGE_LOOP('',(#691,#692,#698,#699));
#701=FACE_BOUND('',#700,.T.);
#702=ADVANCED_FACE('F564',(#674,#685,#701),#663,.F.);
#703=CARTESIAN_POINT('',(0.,101.6,0.));
#704=DIRECTION('',(0.,1.,0.));
#705=DIRECTION('',(0.,0.,1.));
#706=AXIS2_PLACEMENT_3D('',#703,#704,#705);
#707=PLANE('',#706);
#708=ORIENTED_EDGE('',*,*,#564,.T.);
#709=ORIENTED_EDGE('',*,*,#622,.T.);
#710=ORIENTED_EDGE('',*,*,#653,.T.);
#711=ORIENTED_EDGE('',*,*,#697,.T.);
#712=EDGE_LOOP('',(#708,#709,#710,#711));
#713=FACE_BOUND('',#712,.T.);
#714=ADVANCED_FACE('F579',(#713),#707,.T.);
#715=CARTESIAN_POINT('',(0.,0.,0.));
#716=DIRECTION('',(0.,1.,0.));
#717=DIRECTION('',(0.,0.,1.));
#718=AXIS2_PLACEMENT_3D('',#715,#716,#717);
#719=PLANE('',#718);
#720=ORIENTED_EDGE('',*,*,#548,.F.);
#721=ORIENTED_EDGE('',*,*,#690,.F.);
#722=ORIENTED_EDGE('',*,*,#639,.F.);
#723=ORIENTED_EDGE('',*,*,#608,.F.);
#724=EDGE_LOOP('',(#720,#721,#722,#723));
#725=FACE_BOUND('',#724,.T.);
#726=ADVANCED_FACE('F569',(#725),#719,.F.);
#727=CARTESIAN_POINT('',(-107.95,33.8666666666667,63.5));
#728=DIRECTION('',(0.,0.,1.));
#729=DIRECTION('',(1.,0.,0.));
#730=AXIS2_PLACEMENT_3D('',#727,#728,#729);
#731=CYLINDRICAL_SURFACE('',#730,2.2479);
#732=CARTESIAN_POINT('',(-107.95,33.8666666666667,33.528));
#733=DIRECTION('',(0.,0.,1.));
#734=DIRECTION('',(1.,0.,0.));
#735=AXIS2_PLACEMENT_3D('',#732,#733,#734);
#736=CIRCLE('',#735,2.2479);
#737=CARTESIAN_POINT('',(-105.7021,33.8666666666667,33.528));
#738=VERTEX_POINT('',#737);
#739=EDGE_CURVE('E540',#738,#738,#736,.T.);
#740=ORIENTED_EDGE('',*,*,#739,.F.);
#741=EDGE_LOOP('',(#740));
#742=FACE_BOUND('',#741,.T.);
#743=ORIENTED_EDGE('',*,*,#682,.F.);
#744=EDGE_LOOP('',(#743));
#745=FACE_BOUND('',#744,.T.);
#746=ADVANCED_FACE('F566',(#742,#745),#731,.F.);
#747=CARTESIAN_POINT('',(-107.95,33.8666666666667,33.528));
#748=DIRECTION('',(0.,0.,1.));
#749=DIRECTION('',(1.,0.,0.));
#750=AXIS2_PLACEMENT_3D('',#747,#748,#749);
#751=CONICAL_SURFACE('',#750,2.2479,1.02974425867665);
#752=CARTESIAN_POINT('',(-107.95,33.8666666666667,32.1773254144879));
#753=VERTEX_POINT('',#752);
#754=VERTEX_LOOP('',#753);
#755=FACE_BOUND('',#754,.T.);
#756=ORIENTED_EDGE('',*,*,#739,.T.);
#757=EDGE_LOOP('',(#756));
#758=FACE_BOUND('',#757,.T.);
#759=ADVANCED_FACE('F568',(#755,#758),#751,.F.);
#760=CARTESIAN_POINT('',(-107.95,67.7333333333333,63.5));
#761=DIRECTION('',(0.,0.,1.));
#762=DIRECTION('',(1.,0.,0.));
#763=AXIS2_PLACEMENT_3D('',#760,#761,#762);
#764=CYLINDRICAL_SURFACE('',#763,2.2479);
#765=CARTESIAN_POINT('',(-107.95,67.7333333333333,33.528));
#766=DIRECTION('',(0.,0.,1.));
#767=DIRECTION('',(1.,0.,0.));
#768=AXIS2_PLACEMENT_3D('',#765,#766,#767);
#769=CIRCLE('',#768,2.2479);
#770=CARTESIAN_POINT('',(-105.7021,67.7333333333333,33.528));
#771=VERTEX_POINT('',#770);
#772=EDGE_CURVE('E537',#771,#771,#769,.T.);
#773=ORIENTED_EDGE('',*,*,#772,.F.);
#774=EDGE_LOOP('',(#773));
#775=FACE_BOUND('',#774,.T.);
#776=ORIENTED_EDGE('',*,*,#671,.F.);
#777=EDGE_LOOP('',(#776));
#778=FACE_BOUND('',#777,.T.);
#779=ADVANCED_FACE('F576',(#775,#778),#764,.F.);
#780=CARTESIAN_POINT('',(-107.95,67.7333333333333,33.528));
#781=DIRECTION('',(0.,0.,1.));
#782=DIRECTION('',(1.,0.,0.));
#783=AXIS2_PLACEMENT_3D('',#780,#781,#782);
#784=CONICAL_SURFACE('',#783,2.2479,1.02974425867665);
#785=CARTESIAN_POINT('',(-107.95,67.7333333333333,32.1773254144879));
#786=VERTEX_POINT('',#785);
#787=VERTEX_LOOP('',#786);
#788=FACE_BOUND('',#787,.T.);
#789=ORIENTED_EDGE('',*,*,#772,.T.);
#790=EDGE_LOOP('',(#789));
#791=FACE_BOUND('',#790,.T.);
#792=ADVANCED_FACE('F636',(#788,#791),#784,.F.);
#793=CARTESIAN_POINT('',(-107.95,67.7333333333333,-63.5));
#794=DIRECTION('',(0.,0.,-1.));
#795=DIRECTION('',(1.,0.,0.));
#796=AXIS2_PLACEMENT_3D('',#793,#794,#795);
#797=CYLINDRICAL_SURFACE('',#796,2.2479);
#798=CARTESIAN_POINT('',(-107.95,67.7333333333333,-33.528));
#799=DIRECTION('',(0.,0.,1.));
#800=DIRECTION('',(1.,0.,0.));
#801=AXIS2_PLACEMENT_3D('',#798,#799,#800);
#802=CIRCLE('',#801,2.2479);
#803=CARTESIAN_POINT('',(-105.7021,67.7333333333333,-33.528));
#804=VERTEX_POINT('',#803);
#805=EDGE_CURVE('E530',#804,#804,#802,.T.);
#806=ORIENTED_EDGE('',*,*,#805,.T.);
#807=EDGE_LOOP('',(#806));
#808=FACE_BOUND('',#807,.T.);
#809=ORIENTED_EDGE('',*,*,#598,.T.);
#810=EDGE_LOOP('',(#809));
#811=FACE_BOUND('',#810,.T.);
#812=ADVANCED_FACE('F645',(#808,#811),#797,.F.);
#813=CARTESIAN_POINT('',(-107.95,67.7333333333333,-33.528));
#814=DIRECTION('',(0.,0.,-1.));
#815=DIRECTION('',(1.,0.,0.));
#816=AXIS2_PLACEMENT_3D('',#813,#814,#815);
#817=CONICAL_SURFACE('',#816,2.2479,1.02974425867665);
#818=CARTESIAN_POINT('',(-107.95,67.7333333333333,-32.1773254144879));
#819=VERTEX_POINT('',#818);
#820=VERTEX_LOOP('',#819);
#821=FACE_BOUND('',#820,.T.);
#822=ORIENTED_EDGE('',*,*,#805,.F.);
#823=EDGE_LOOP('',(#822));
#824=FACE_BOUND('',#823,.T.);
#825=ADVANCED_FACE('F660',(#821,#824),#817,.F.);
#826=CARTESIAN_POINT('',(-107.95,33.8666666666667,-63.5));
#827=DIRECTION('',(0.,0.,-1.));
#828=DIRECTION('',(1.,0.,0.));
#829=AXIS2_PLACEMENT_3D('',#826,#827,#828);
#830=CYLINDRICAL_SURFACE('',#829,2.2479);
#831=CARTESIAN_POINT('',(-107.95,33.8666666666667,-33.528));
#832=DIRECTION('',(0.,0.,1.));
#833=DIRECTION('',(1.,0.,0.));
#834=AXIS2_PLACEMENT_3D('',#831,#832,#833);
#835=CIRCLE('',#834,2.2479);
#836=CARTESIAN_POINT('',(-105.7021,33.8666666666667,-33.528));
#837=VERTEX_POINT('',#836);
#838=EDGE_CURVE('E524',#837,#837,#835,.T.);
#839=ORIENTED_EDGE('',*,*,#838,.T.);
#840=EDGE_LOOP('',(#839));
#841=FACE_BOUND('',#840,.T.);
#842=ORIENTED_EDGE('',*,*,#587,.T.);
#843=EDGE_LOOP('',(#842));
#844=FACE_BOUND('',#843,.T.);
#845=ADVANCED_FACE('F520',(#841,#844),#830,.F.);
#846=CARTESIAN_POINT('',(-107.95,33.8666666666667,-33.528));
#847=DIRECTION('',(0.,0.,-1.));
#848=DIRECTION('',(1.,0.,0.));
#849=AXIS2_PLACEMENT_3D('',#846,#847,#848);
#850=CONICAL_SURFACE('',#849,2.2479,1.02974425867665);
#851=CARTESIAN_POINT('',(-107.95,33.8666666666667,-32.1773254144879));
#852=VERTEX_POINT('',#851);
#853=VERTEX_LOOP('',#852);
#854=FACE_BOUND('',#853,.T.);
#855=ORIENTED_EDGE('',*,*,#838,.F.);
#856=EDGE_LOOP('',(#855));
#857=FACE_BOUND('',#856,.T.);
#858=ADVANCED_FACE('F517',(#854,#857),#850,.F.);
#859=CLOSED_SHELL('',(#574,#627,#658,#702,#714,#726,#746,#759,#779,#792,#812,#825,#845,#858));
#860=MANIFOLD_SOLID_BREP('B37',#859);
#861=CARTESIAN_POINT('',(101.6,101.6,-50.8));
#862=DIRECTION('',(1.,0.,0.));
#863=DIRECTION('',(0.,0.,-1.));
#864=AXIS2_PLACEMENT_3D('',#861,#862,#863);
#865=PLANE('',#864);
#866=DIRECTION('',(0.,0.,1.));
#867=VECTOR('',#866,1.);
#868=CARTESIAN_POINT('',(101.6,0.,-50.8));
#869=LINE('',#868,#867);
#870=CARTESIAN_POINT('',(101.6,0.,-50.8));
#871=VERTEX_POINT('',#870);
#872=CARTESIAN_POINT('',(101.6,0.,50.8));
#873=VERTEX_POINT('',#872);
#874=EDGE_CURVE('E820',#871,#873,#869,.T.);
#875=ORIENTED_EDGE('',*,*,#874,.T.);
#876=DIRECTION('',(0.,-1.,0.));
#877=VECTOR('',#876,1.);
#878=CARTESIAN_POINT('',(101.6,101.6,50.8));
#879=LINE('',#878,#877);
#880=CARTESIAN_POINT('',(101.6,101.6,50.8));
#881=VERTEX_POINT('',#880);
#882=EDGE_CURVE('E453',#881,#873,#879,.T.);
#883=ORIENTED_EDGE('',*,*,#882,.F.);
#884=DIRECTION('',(0.,0.,1.));
#885=VECTOR('',#884,1.);
#886=CARTESIAN_POINT('',(101.6,101.6,-50.8));
#887=LINE('',#886,#885);
#888=CARTESIAN_POINT('',(101.6,101.6,-50.8));
#889=VERTEX_POINT('',#888);
#890=EDGE_CURVE('E813',#889,#881,#887,.T.);
#891=ORIENTED_EDGE('',*,*,#890,.F.);
#892=DIRECTION('',(0.,-1.,0.));
#893=VECTOR('',#892,1.);
#894=CARTESIAN_POINT('',(101.6,101.6,-50.8));
#895=LINE('',#894,#893);
#896=EDGE_CURVE('E819',#889,#871,#895,.T.);
#897=ORIENTED_EDGE('',*,*,#896,.T.);
#898=EDGE_LOOP('',(#875,#883,#891,#897));
#899=FACE_BOUND('',#898,.T.);
#900=ADVANCED_FACE('F724',(#899),#865,.F.);
#901=CARTESIAN_POINT('',(101.6,101.6,50.8));
#902=DIRECTION('',(0.,0.,-1.));
#903=DIRECTION('',(-1.,0.,0.));
#904=AXIS2_PLACEMENT_3D('',#901,#902,#903);
#905=PLANE('',#904);
#906=CARTESIAN_POINT('',(107.95,67.7333333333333,50.8));
#907=DIRECTION('',(0.,0.,-1.));
#908=DIRECTION('',(-1.,0.,0.));
#909=AXIS2_PLACEMENT_3D('',#906,#907,#908);
#910=CIRCLE('',#909,2.2479);
#911=CARTESIAN_POINT('',(105.7021,67.7333333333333,50.8));
#912=VERTEX_POINT('',#911);
#913=EDGE_CURVE('E727',#912,#912,#910,.T.);
#914=ORIENTED_EDGE('',*,*,#913,.T.);
#915=EDGE_LOOP('',(#914));
#916=FACE_BOUND('',#915,.T.);
#917=CARTESIAN_POINT('',(107.95,33.8666666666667,50.8));
#918=DIRECTION('',(0.,0.,-1.));
#919=DIRECTION('',(-1.,0.,0.));
#920=AXIS2_PLACEMENT_3D('',#917,#918,#919);
#921=CIRCLE('',#920,2.2479);
#922=CARTESIAN_POINT('',(105.7021,33.8666666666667,50.8));
#923=VERTEX_POINT('',#922);
#924=EDGE_CURVE('E812',#923,#923,#921,.T.);
#925=ORIENTED_EDGE('',*,*,#924,.T.);
#926=EDGE_LOOP('',(#925));
#927=FACE_BOUND('',#926,.T.);
#928=DIRECTION('',(1.,0.,0.));
#929=VECTOR('',#928,1.);
#930=CARTESIAN_POINT('',(101.6,0.,50.8));
#931=LINE('',#930,#929);
#932=CARTESIAN_POINT('',(114.3,0.,50.8));
#933=VERTEX_POINT('',#932);
#934=EDGE_CURVE('E823',#873,#933,#931,.T.);
#935=ORIENTED_EDGE('',*,*,#934,.T.);
#936=DIRECTION('',(0.,-1.,0.));
#937=VECTOR('',#936,1.);
#938=CARTESIAN_POINT('',(114.3,101.6,50.8));
#939=LINE('',#938,#937);
#940=CARTESIAN_POINT('',(114.3,101.6,50.8));
#941=VERTEX_POINT('',#940);
#942=EDGE_CURVE('E733',#941,#933,#939,.T.);
#943=ORIENTED_EDGE('',*,*,#942,.F.);
#944=DIRECTION('',(1.,0.,0.));
#945=VECTOR('',#944,1.);
#946=CARTESIAN_POINT('',(101.6,101.6,50.8));
#947=LINE('',#946,#945);
#948=EDGE_CURVE('E773',#881,#941,#947,.T.);
#949=ORIENTED_EDGE('',*,*,#948,.F.);
#950=ORIENTED_EDGE('',*,*,#882,.T.);
#951=EDGE_LOOP('',(#935,#943,#949,#950));
#952=FACE_BOUND('',#951,.T.);
#953=ADVANCED_FACE('F833',(#916,#927,#952),#905,.F.);
#954=CARTESIAN_POINT('',(114.3,101.6,-50.8));
#955=DIRECTION('',(-1.,0.,0.));
#956=DIRECTION('',(0.,0.,1.));
#957=AXIS2_PLACEMENT_3D('',#954,#955,#956);
#958=PLANE('',#957);
#959=DIRECTION('',(0.,0.,-1.));
#960=VECTOR('',#959,1.);
#961=CARTESIAN_POINT('',(114.3,0.,-50.8));
#962=LINE('',#961,#960);
#963=CARTESIAN_POINT('',(114.3,0.,-50.8));
#964=VERTEX_POINT('',#963);
#965=EDGE_CURVE('E760',#933,#964,#962,.T.);
#966=ORIENTED_EDGE('',*,*,#965,.T.);
#967=DIRECTION('',(0.,-1.,0.));
#968=VECTOR('',#967,1.);
#969=CARTESIAN_POINT('',(114.3,101.6,-50.8));
#970=LINE('',#969,#968);
#971=CARTESIAN_POINT('',(114.3,101.6,-50.8));
#972=VERTEX_POINT('',#971);
#973=EDGE_CURVE('E828',#972,#964,#970,.T.);
#974=ORIENTED_EDGE('',*,*,#973,.F.);
#975=DIRECTION('',(0.,0.,-1.));
#976=VECTOR('',#975,1.);
#977=CARTESIAN_POINT('',(114.3,101.6,-50.8));
#978=LINE('',#977,#976);
#979=EDGE_CURVE('E816',#941,#972,#978,.T.);
#980=ORIENTED_EDGE('',*,*,#979,.F.);
#981=ORIENTED_EDGE('',*,*,#942,.T.);
#982=EDGE_LOOP('',(#966,#974,#980,#981));
#983=FACE_BOUND('',#982,.T.);
#984=ADVANCED_FACE('F858',(#983),#958,.F.);
#985=CARTESIAN_POINT('',(101.6,101.6,-50.8));
#986=DIRECTION('',(0.,0.,1.));
#987=DIRECTION('',(1.,0.,0.));
#988=AXIS2_PLACEMENT_3D('',#985,#986,#987);
#989=PLANE('',#988);
#990=CARTESIAN_POINT('',(107.95,33.8666666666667,-50.8));
#991=DIRECTION('',(0.,0.,-1.));
#992=DIRECTION('',(-1.,0.,0.));
#993=AXIS2_PLACEMENT_3D('',#990,#991,#992);
#994=CIRCLE('',#993,2.2479);
#995=CARTESIAN_POINT('',(105.7021,33.8666666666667,-50.8));
#996=VERTEX_POINT('',#995);
#997=EDGE_CURVE('E796',#996,#996,#994,.T.);
#998=ORIENTED_EDGE('',*,*,#997,.F.);
#999=EDGE_LOOP('',(#998));
#1000=FACE_BOUND('',#999,.T.);
#1001=CARTESIAN_POINT('',(107.95,67.7333333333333,-50.8));
#1002=DIRECTION('',(0.,0.,-1.));
#1003=DIRECTION('',(-1.,0.,0.));
#1004=AXIS2_PLACEMENT_3D('',#1001,#1002,#1003);
#1005=CIRCLE('',#1004,2.2479);
#1006=CARTESIAN_POINT('',(105.7021,67.7333333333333,-50.8));
#1007=VERTEX_POINT('',#1006);
#1008=EDGE_CURVE('E795',#1007,#1007,#1005,.T.);
#1009=ORIENTED_EDGE('',*,*,#1008,.F.);
#1010=EDGE_LOOP('',(#1009));
#1011=FACE_BOUND('',#1010,.T.);
#1012=DIRECTION('',(-1.,0.,0.));
#1013=VECTOR('',#1012,1.);
#1014=CARTESIAN_POINT('',(101.6,0.,-50.8));
#1015=LINE('',#1014,#1013);
#1016=EDGE_CURVE('E766',#964,#871,#1015,.T.);
#1017=ORIENTED_EDGE('',*,*,#1016,.T.);
#1018=ORIENTED_EDGE('',*,*,#896,.F.);
#1019=DIRECTION('',(-1.,0.,0.));
#1020=VECTOR('',#1019,1.);
#1021=CARTESIAN_POINT('',(101.6,101.6,-50.8));
#1022=LINE('',#1021,#1020);
#1023=EDGE_CURVE('E742',#972,#889,#1022,.T.);
#1024=ORIENTED_EDGE('',*,*,#1023,.F.);
#1025=ORIENTED_EDGE('',*,*,#973,.T.);
#1026=EDGE_LOOP('',(#1017,#1018,#1024,#1025));
#1027=FACE_BOUND('',#1026,.T.);
#1028=ADVANCED_FACE('F865',(#1000,#1011,#1027),#989,.F.);
#1029=CARTESIAN_POINT('',(0.,101.6,0.));
#1030=DIRECTION('',(0.,1.,0.));
#1031=DIRECTION('',(0.,0.,1.));
#1032=AXIS2_PLACEMENT_3D('',#1029,#1030,#1031);
#1033=PLANE('',#1032);
#1034=ORIENTED_EDGE('',*,*,#890,.T.);
#1035=ORIENTED_EDGE('',*,*,#948,.T.);
#1036=ORIENTED_EDGE('',*,*,#979,.T.);
#1037=ORIENTED_EDGE('',*,*,#1023,.T.);
#1038=EDGE_LOOP('',(#1034,#1035,#1036,#1037));
#1039=FACE_BOUND('',#1038,.T.);
#1040=ADVANCED_FACE('F848',(#1039),#1033,.T.);
#1041=CARTESIAN_POINT('',(0.,0.,0.));
#1042=DIRECTION('',(0.,1.,0.));
#1043=DIRECTION('',(0.,0.,1.));
#1044=AXIS2_PLACEMENT_3D('',#1041,#1042,#1043);
#1045=PLANE('',#1044);
#1046=ORIENTED_EDGE('',*,*,#874,.F.);
#1047=ORIENTED_EDGE('',*,*,#1016,.F.);
#1048=ORIENTED_EDGE('',*,*,#965,.F.);
#1049=ORIENTED_EDGE('',*,*,#934,.F.);
#1050=EDGE_LOOP('',(#1046,#1047,#1048,#1049));
#1051=FACE_BOUND('',#1050,.T.);
#1052=ADVANCED_FACE('F838',(#1051),#1045,.F.);
#1053=CARTESIAN_POINT('',(107.95,33.8666666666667,63.5));
#1054=DIRECTION('',(0.,0.,1.));
#1055=DIRECTION('',(1.,0.,0.));
#1056=AXIS2_PLACEMENT_3D('',#1053,#1054,#1055);
#1057=CYLINDRICAL_SURFACE('',#1056,2.2479);
#1058=CARTESIAN_POINT('',(107.95,33.8666666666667,33.528));
#1059=DIRECTION('',(0.,0.,1.));
#1060=DIRECTION('',(1.,0.,0.));
#1061=AXIS2_PLACEMENT_3D('',#1058,#1059,#1060);
#1062=CIRCLE('',#1061,2.2479);
#1063=CARTESIAN_POINT('',(110.1979,33.8666666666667,33.528));
#1064=VERTEX_POINT('',#1063);
#1065=EDGE_CURVE('E809',#1064,#1064,#1062,.T.);
#1066=ORIENTED_EDGE('',*,*,#1065,.F.);
#1067=EDGE_LOOP('',(#1066));
#1068=FACE_BOUND('',#1067,.T.);
#1069=ORIENTED_EDGE('',*,*,#924,.F.);
#1070=EDGE_LOOP('',(#1069));
#1071=FACE_BOUND('',#1070,.T.);
#1072=ADVANCED_FACE('F835',(#1068,#1071),#1057,.F.);
#1073=CARTESIAN_POINT('',(107.95,33.8666666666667,33.528));
#1074=DIRECTION('',(0.,0.,1.));
#1075=DIRECTION('',(1.,0.,0.));
#1076=AXIS2_PLACEMENT_3D('',#1073,#1074,#1075);
#1077=CONICAL_SURFACE('',#1076,2.2479,1.02974425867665);
#1078=CARTESIAN_POINT('',(107.95,33.8666666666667,32.1773254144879));
#1079=VERTEX_POINT('',#1078);
#1080=VERTEX_LOOP('',#1079);
#1081=FACE_BOUND('',#1080,.T.);
#1082=ORIENTED_EDGE('',*,*,#1065,.T.);
#1083=EDGE_LOOP('',(#1082));
#1084=FACE_BOUND('',#1083,.T.);
#1085=ADVANCED_FACE('F837',(#1081,#1084),#1077,.F.);
#1086=CARTESIAN_POINT('',(107.95,67.7333333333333,63.5));
#1087=DIRECTION('',(0.,0.,1.));
#1088=DIRECTION('',(1.,0.,0.));
#1089=AXIS2_PLACEMENT_3D('',#1086,#1087,#1088);
#1090=CYLINDRICAL_SURFACE('',#1089,2.2479);
#1091=CARTESIAN_POINT('',(107.95,67.7333333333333,33.528));
#1092=DIRECTION('',(0.,0.,1.));
#1093=DIRECTION('',(1.,0.,0.));
#1094=AXIS2_PLACEMENT_3D('',#1091,#1092,#1093);
#1095=CIRCLE('',#1094,2.2479);
#1096=CARTESIAN_POINT('',(110.1979,67.7333333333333,33.528));
#1097=VERTEX_POINT('',#1096);
#1098=EDGE_CURVE('E806',#1097,#1097,#1095,.T.);
#1099=ORIENTED_EDGE('',*,*,#1098,.F.);
#1100=EDGE_LOOP('',(#1099));
#1101=FACE_BOUND('',#1100,.T.);
#1102=ORIENTED_EDGE('',*,*,#913,.F.);
#1103=EDGE_LOOP('',(#1102));
#1104=FACE_BOUND('',#1103,.T.);
#1105=ADVANCED_FACE('F845',(#1101,#1104),#1090,.F.);
#1106=CARTESIAN_POINT('',(107.95,67.7333333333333,33.528));
#1107=DIRECTION('',(0.,0.,1.));
#1108=DIRECTION('',(1.,0.,0.));
#1109=AXIS2_PLACEMENT_3D('',#1106,#1107,#1108);
#1110=CONICAL_SURFACE('',#1109,2.2479,1.02974425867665);
#1111=CARTESIAN_POINT('',(107.95,67.7333333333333,32.1773254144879));
#1112=VERTEX_POINT('',#1111);
#1113=VERTEX_LOOP('',#1112);
#1114=FACE_BOUND('',#1113,.T.);
#1115=ORIENTED_EDGE('',*,*,#1098,.T.);
#1116=EDGE_LOOP('',(#1115));
#1117=FACE_BOUND('',#1116,.T.);
#1118=ADVANCED_FACE('F889',(#1114,#1117),#1110,.F.);
#1119=CARTESIAN_POINT('',(107.95,67.7333333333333,-63.5));
#1120=DIRECTION('',(0.,0.,-1.));
#1121=DIRECTION('',(1.,0.,0.));
#1122=AXIS2_PLACEMENT_3D('',#1119,#1120,#1121);
#1123=CYLINDRICAL_SURFACE('',#1122,2.2479);
#1124=CARTESIAN_POINT('',(107.95,67.7333333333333,-33.528));
#1125=DIRECTION('',(0.,0.,1.));
#1126=DIRECTION('',(1.,0.,0.));
#1127=AXIS2_PLACEMENT_3D('',#1124,#1125,#1126);
#1128=CIRCLE('',#1127,2.2479);
#1129=CARTESIAN_POINT('',(110.1979,67.7333333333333,-33.528));
#1130=VERTEX_POINT('',#1129);
#1131=EDGE_CURVE('E799',#1130,#1130,#1128,.T.);
#1132=ORIENTED_EDGE('',*,*,#1131,.T.);
#1133=EDGE_LOOP('',(#1132));
#1134=FACE_BOUND('',#1133,.T.);
#1135=ORIENTED_EDGE('',*,*,#1008,.T.);
#1136=EDGE_LOOP('',(#1135));
#1137=FACE_BOUND('',#1136,.T.);
#1138=ADVANCED_FACE('F894',(#1134,#1137),#1123,.F.);
#1139=CARTESIAN_POINT('',(107.95,67.7333333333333,-33.528));
#1140=DIRECTION('',(0.,0.,-1.));
#1141=DIRECTION('',(1.,0.,0.));
#1142=AXIS2_PLACEMENT_3D('',#1139,#1140,#1141);
#1143=CONICAL_SURFACE('',#1142,2.2479,1.02974425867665);
#1144=CARTESIAN_POINT('',(107.95,67.7333333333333,-32.1773254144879));
#1145=VERTEX_POINT('',#1144);
#1146=VERTEX_LOOP('',#1145);
#1147=FACE_BOUND('',#1146,.T.);
#1148=ORIENTED_EDGE('',*,*,#1131,.F.);
#1149=EDGE_LOOP('',(#1148));
#1150=FACE_BOUND('',#1149,.T.);
#1151=ADVANCED_FACE('F899',(#1147,#1150),#1143,.F.);
#1152=CARTESIAN_POINT('',(107.95,33.8666666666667,-63.5));
#1153=DIRECTION('',(0.,0.,-1.));
#1154=DIRECTION('',(1.,0.,0.));
#1155=AXIS2_PLACEMENT_3D('',#1152,#1153,#1154);
#1156=CYLINDRICAL_SURFACE('',#1155,2.2479);
#1157=CARTESIAN_POINT('',(107.95,33.8666666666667,-33.528));
#1158=DIRECTION('',(0.,0.,1.));
#1159=DIRECTION('',(1.,0.,0.));
#1160=AXIS2_PLACEMENT_3D('',#1157,#1158,#1159);
#1161=CIRCLE('',#1160,2.2479);
#1162=CARTESIAN_POINT('',(110.1979,33.8666666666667,-33.528));
#1163=VERTEX_POINT('',#1162);
#1164=EDGE_CURVE('E793',#1163,#1163,#1161,.T.);
#1165=ORIENTED_EDGE('',*,*,#1164,.T.);
#1166=EDGE_LOOP('',(#1165));
#1167=FACE_BOUND('',#1166,.T.);
#1168=ORIENTED_EDGE('',*,*,#997,.T.);
#1169=EDGE_LOOP('',(#1168));
#1170=FACE_BOUND('',#1169,.T.);
#1171=ADVANCED_FACE('F789',(#1167,#1170),#1156,.F.);
#1172=CARTESIAN_POINT('',(107.95,33.8666666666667,-33.528));
#1173=DIRECTION('',(0.,0.,-1.));
#1174=DIRECTION('',(1.,0.,0.));
#1175=AXIS2_PLACEMENT_3D('',#1172,#1173,#1174);
#1176=CONICAL_SURFACE('',#1175,2.2479,1.02974425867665);
#1177=CARTESIAN_POINT('',(107.95,33.8666666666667,-32.1773254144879));
#1178=VERTEX_POINT('',#1177);
#1179=VERTEX_LOOP('',#1178);
#1180=FACE_BOUND('',#1179,.T.);
#1181=ORIENTED_EDGE('',*,*,#1164,.F.);
#1182=EDGE_LOOP('',(#1181));
#1183=FACE_BOUND('',#1182,.T.);
#1184=ADVANCED_FACE('F786',(#1180,#1183),#1176,.F.);
#1185=CLOSED_SHELL('',(#900,#953,#984,#1028,#1040,#1052,#1072,#1085,#1105,#1118,#1138,#1151,
#1171,#1184));
#1186=MANIFOLD_SOLID_BREP('B170',#1185);
#1187=CARTESIAN_POINT('',(-114.3,101.6,50.8));
#1188=DIRECTION('',(1.,0.,0.));
#1189=DIRECTION('',(0.,0.,-1.));
#1190=AXIS2_PLACEMENT_3D('',#1187,#1188,#1189);
#1191=PLANE('',#1190);
#1192=DIRECTION('',(0.,0.,1.));
#1193=VECTOR('',#1192,1.);
#1194=CARTESIAN_POINT('',(-114.3,0.,50.8));
#1195=LINE('',#1194,#1193);
#1196=CARTESIAN_POINT('',(-114.3,0.,50.8));
#1197=VERTEX_POINT('',#1196);
#1198=CARTESIAN_POINT('',(-114.3,0.,63.5));
#1199=VERTEX_POINT('',#1198);
#1200=EDGE_CURVE('E1099',#1197,#1199,#1195,.T.);
#1201=ORIENTED_EDGE('',*,*,#1200,.T.);
#1202=DIRECTION('',(0.,-1.,0.));
#1203=VECTOR('',#1202,1.);
#1204=CARTESIAN_POINT('',(-114.3,101.6,63.5));
#1205=LINE('',#1204,#1203);
#1206=CARTESIAN_POINT('',(-114.3,101.6,63.5));
#1207=VERTEX_POINT('',#1206);
#1208=EDGE_CURVE('E722',#1207,#1199,#1205,.T.);
#1209=ORIENTED_EDGE('',*,*,#1208,.F.);
#1210=DIRECTION('',(0.,0.,1.));
#1211=VECTOR('',#1210,1.);
#1212=CARTESIAN_POINT('',(-114.3,101.6,50.8));
#1213=LINE('',#1212,#1211);
#1214=CARTESIAN_POINT('',(-114.3,101.6,50.8));
#1215=VERTEX_POINT('',#1214);
#1216=EDGE_CURVE('E1092',#1215,#1207,#1213,.T.);
#1217=ORIENTED_EDGE('',*,*,#1216,.F.);
#1218=DIRECTION('',(0.,-1.,0.));
#1219=VECTOR('',#1218,1.);
#1220=CARTESIAN_POINT('',(-114.3,101.6,50.8));
#1221=LINE('',#1220,#1219);
#1222=EDGE_CURVE('E1098',#1215,#1197,#1221,.T.);
#1223=ORIENTED_EDGE('',*,*,#1222,.T.);
#1224=EDGE_LOOP('',(#1201,#1209,#1217,#1223));
#1225=FACE_BOUND('',#1224,.T.);
#1226=ADVANCED_FACE('F992',(#1225),#1191,.F.);
#1227=CARTESIAN_POINT('',(-114.3,101.6,63.5));
#1228=DIRECTION('',(0.,0.,-1.));
#1229=DIRECTION('',(-1.,0.,0.));
#1230=AXIS2_PLACEMENT_3D('',#1227,#1228,#1229);
#1231=PLANE('',#1230);
#1232=CARTESIAN_POINT('',(-107.95,67.7333333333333,63.5));
#1233=DIRECTION('',(0.,0.,1.));
#1234=DIRECTION('',(1.,0.,0.));
#1235=AXIS2_PLACEMENT_3D('',#1232,#1233,#1234);
#1236=CIRCLE('',#1235,4.21639999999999);
#1237=CARTESIAN_POINT('',(-103.7336,67.7333333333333,63.5));
#1238=VERTEX_POINT('',#1237);
#1239=EDGE_CURVE('E1064',#1238,#1238,#1236,.T.);
#1240=ORIENTED_EDGE('',*,*,#1239,.F.);
#1241=EDGE_LOOP('',(#1240));
#1242=FACE_BOUND('',#1241,.T.);
#1243=CARTESIAN_POINT('',(-107.95,33.8666666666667,63.5));
#1244=DIRECTION('',(0.,0.,1.));
#1245=DIRECTION('',(1.,0.,0.));
#1246=AXIS2_PLACEMENT_3D('',#1243,#1244,#1245);
#1247=CIRCLE('',#1246,4.21639999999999);
#1248=CARTESIAN_POINT('',(-103.7336,33.8666666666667,63.5));
#1249=VERTEX_POINT('',#1248);
#1250=EDGE_CURVE('E1071',#1249,#1249,#1247,.T.);
#1251=ORIENTED_EDGE('',*,*,#1250,.F.);
#1252=EDGE_LOOP('',(#1251));
#1253=FACE_BOUND('',#1252,.T.);
#1254=CARTESIAN_POINT('',(107.95,67.7333333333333,63.5));
#1255=DIRECTION('',(0.,0.,1.));
#1256=DIRECTION('',(1.,0.,0.));
#1257=AXIS2_PLACEMENT_3D('',#1254,#1255,#1256);
#1258=CIRCLE('',#1257,4.21639999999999);
#1259=CARTESIAN_POINT('',(112.1664,67.7333333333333,63.5));
#1260=VERTEX_POINT('',#1259);
#1261=EDGE_CURVE('E1078',#1260,#1260,#1258,.T.);
#1262=ORIENTED_EDGE('',*,*,#1261,.F.);
#1263=EDGE_LOOP('',(#1262));
#1264=FACE_BOUND('',#1263,.T.);
#1265=CARTESIAN_POINT('',(107.95,33.8666666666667,63.5));
#1266=DIRECTION('',(0.,0.,1.));
#1267=DIRECTION('',(1.,0.,0.));
#1268=AXIS2_PLACEMENT_3D('',#1265,#1266,#1267);
#1269=CIRCLE('',#1268,4.21639999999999);
#1270=CARTESIAN_POINT('',(112.1664,33.8666666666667,63.5));
#1271=VERTEX_POINT('',#1270);
#1272=EDGE_CURVE('E1085',#1271,#1271,#1269,.T.);
#1273=ORIENTED_EDGE('',*,*,#1272,.F.);
#1274=EDGE_LOOP('',(#1273));
#1275=FACE_BOUND('',#1274,.T.);
#1276=DIRECTION('',(1.,0.,0.));
#1277=VECTOR('',#1276,1.);
#1278=CARTESIAN_POINT('',(-114.3,0.,63.5));
#1279=LINE('',#1278,#1277);
#1280=CARTESIAN_POINT('',(114.3,0.,63.5));
#1281=VERTEX_POINT('',#1280);
#1282=EDGE_CURVE('E1102',#1199,#1281,#1279,.T.);
#1283=ORIENTED_EDGE('',*,*,#1282,.T.);
#1284=DIRECTION('',(0.,-1.,0.));
#1285=VECTOR('',#1284,1.);
#1286=CARTESIAN_POINT('',(114.3,101.6,63.5));
#1287=LINE('',#1286,#1285);
#1288=CARTESIAN_POINT('',(114.3,101.6,63.5));
#1289=VERTEX_POINT('',#1288);
#1290=EDGE_CURVE('E1001',#1289,#1281,#1287,.T.);
#1291=ORIENTED_EDGE('',*,*,#1290,.F.);
#1292=DIRECTION('',(1.,0.,0.));
#1293=VECTOR('',#1292,1.);
#1294=CARTESIAN_POINT('',(-114.3,101.6,63.5));
#1295=LINE('',#1294,#1293);
#1296=EDGE_CURVE('E1041',#1207,#1289,#1295,.T.);
#1297=ORIENTED_EDGE('',*,*,#1296,.F.);
#1298=ORIENTED_EDGE('',*,*,#1208,.T.);
#1299=EDGE_LOOP('',(#1283,#1291,#1297,#1298));
#1300=FACE_BOUND('',#1299,.T.);
#1301=ADVANCED_FACE('F1140',(#1242,#1253,#1264,#1275,#1300),#1231,.F.);
#1302=CARTESIAN_POINT('',(114.3,101.6,50.8));
#1303=DIRECTION('',(-1.,0.,0.));
#1304=DIRECTION('',(0.,0.,1.));
#1305=AXIS2_PLACEMENT_3D('',#1302,#1303,#1304);
#1306=PLANE('',#1305);
#1307=DIRECTION('',(0.,0.,-1.));
#1308=VECTOR('',#1307,1.);
#1309=CARTESIAN_POINT('',(114.3,0.,50.8));
#1310=LINE('',#1309,#1308);
#1311=CARTESIAN_POINT('',(114.3,0.,50.8));
#1312=VERTEX_POINT('',#1311);
#1313=EDGE_CURVE('E1028',#1281,#1312,#1310,.T.);
#1314=ORIENTED_EDGE('',*,*,#1313,.T.);
#1315=DIRECTION('',(0.,-1.,0.));
#1316=VECTOR('',#1315,1.);
#1317=CARTESIAN_POINT('',(114.3,101.6,50.8));
#1318=LINE('',#1317,#1316);
#1319=CARTESIAN_POINT('',(114.3,101.6,50.8));
#1320=VERTEX_POINT('',#1319);
#1321=EDGE_CURVE('E1107',#1320,#1312,#1318,.T.);
#1322=ORIENTED_EDGE('',*,*,#1321,.F.);
#1323=DIRECTION('',(0.,0.,-1.));
#1324=VECTOR('',#1323,1.);
#1325=CARTESIAN_POINT('',(114.3,101.6,50.8));
#1326=LINE('',#1325,#1324);
#1327=EDGE_CURVE('E1095',#1289,#1320,#1326,.T.);
#1328=ORIENTED_EDGE('',*,*,#1327,.F.);
#1329=ORIENTED_EDGE('',*,*,#1290,.T.);
#1330=EDGE_LOOP('',(#1314,#1322,#1328,#1329));
#1331=FACE_BOUND('',#1330,.T.);
#1332=ADVANCED_FACE('F1145',(#1331),#1306,.F.);
#1333=CARTESIAN_POINT('',(-114.3,101.6,50.8));
#1334=DIRECTION('',(0.,0.,1.));
#1335=DIRECTION('',(1.,0.,0.));
#1336=AXIS2_PLACEMENT_3D('',#1333,#1334,#1335);
#1337=PLANE('',#1336);
#1338=CARTESIAN_POINT('',(-107.95,67.7333333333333,50.8));
#1339=DIRECTION('',(0.,0.,1.));
#1340=DIRECTION('',(1.,0.,0.));
#1341=AXIS2_PLACEMENT_3D('',#1338,#1339,#1340);
#1342=CIRCLE('',#1341,2.2479);
#1343=CARTESIAN_POINT('',(-105.7021,67.7333333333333,50.8));
#1344=VERTEX_POINT('',#1343);
#1345=EDGE_CURVE('E1070',#1344,#1344,#1342,.T.);
#1346=ORIENTED_EDGE('',*,*,#1345,.T.);
#1347=EDGE_LOOP('',(#1346));
#1348=FACE_BOUND('',#1347,.T.);
#1349=CARTESIAN_POINT('',(-107.95,33.8666666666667,50.8));
#1350=DIRECTION('',(0.,0.,1.));
#1351=DIRECTION('',(1.,0.,0.));
#1352=AXIS2_PLACEMENT_3D('',#1349,#1350,#1351);
#1353=CIRCLE('',#1352,2.2479);
#1354=CARTESIAN_POINT('',(-105.7021,33.8666666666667,50.8));
#1355=VERTEX_POINT('',#1354);
#1356=EDGE_CURVE('E1077',#1355,#1355,#1353,.T.);
#1357=ORIENTED_EDGE('',*,*,#1356,.T.);
#1358=EDGE_LOOP('',(#1357));
#1359=FACE_BOUND('',#1358,.T.);
#1360=CARTESIAN_POINT('',(107.95,67.7333333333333,50.8));
#1361=DIRECTION('',(0.,0.,1.));
#1362=DIRECTION('',(1.,0.,0.));
#1363=AXIS2_PLACEMENT_3D('',#1360,#1361,#1362);
#1364=CIRCLE('',#1363,2.2479);
#1365=CARTESIAN_POINT('',(110.1979,67.7333333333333,50.8));
#1366=VERTEX_POINT('',#1365);
#1367=EDGE_CURVE('E1084',#1366,#1366,#1364,.T.);
#1368=ORIENTED_EDGE('',*,*,#1367,.T.);
#1369=EDGE_LOOP('',(#1368));
#1370=FACE_BOUND('',#1369,.T.);
#1371=CARTESIAN_POINT('',(107.95,33.8666666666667,50.8));
#1372=DIRECTION('',(0.,0.,1.));
#1373=DIRECTION('',(1.,0.,0.));
#1374=AXIS2_PLACEMENT_3D('',#1371,#1372,#1373);
#1375=CIRCLE('',#1374,2.2479);
#1376=CARTESIAN_POINT('',(110.1979,33.8666666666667,50.8));
#1377=VERTEX_POINT('',#1376);
#1378=EDGE_CURVE('E1091',#1377,#1377,#1375,.T.);
#1379=ORIENTED_EDGE('',*,*,#1378,.T.);
#1380=EDGE_LOOP('',(#1379));
#1381=FACE_BOUND('',#1380,.T.);
#1382=DIRECTION('',(-1.,0.,0.));
#1383=VECTOR('',#1382,1.);
#1384=CARTESIAN_POINT('',(-114.3,0.,50.8));
#1385=LINE('',#1384,#1383);
#1386=EDGE_CURVE('E1034',#1312,#1197,#1385,.T.);
#1387=ORIENTED_EDGE('',*,*,#1386,.T.);
#1388=ORIENTED_EDGE('',*,*,#1222,.F.);
#1389=DIRECTION('',(-1.,0.,0.));
#1390=VECTOR('',#1389,1.);
#1391=CARTESIAN_POINT('',(-114.3,101.6,50.8));
#1392=LINE('',#1391,#1390);
#1393=EDGE_CURVE('E1010',#1320,#1215,#1392,.T.);
#1394=ORIENTED_EDGE('',*,*,#1393,.F.);
#1395=ORIENTED_EDGE('',*,*,#1321,.T.);
#1396=EDGE_LOOP('',(#1387,#1388,#1394,#1395));
#1397=FACE_BOUND('',#1396,.T.);
#1398=ADVANCED_FACE('F1153',(#1348,#1359,#1370,#1381,#1397),#1337,.F.);
#1399=CARTESIAN_POINT('',(0.,101.6,0.));
#1400=DIRECTION('',(0.,1.,0.));
#1401=DIRECTION('',(0.,0.,1.));
#1402=AXIS2_PLACEMENT_3D('',#1399,#1400,#1401);
#1403=PLANE('',#1402);
#1404=ORIENTED_EDGE('',*,*,#1216,.T.);
#1405=ORIENTED_EDGE('',*,*,#1296,.T.);
#1406=ORIENTED_EDGE('',*,*,#1327,.T.);
#1407=ORIENTED_EDGE('',*,*,#1393,.T.);
#1408=EDGE_LOOP('',(#1404,#1405,#1406,#1407));
#1409=FACE_BOUND('',#1408,.T.);
#1410=ADVANCED_FACE('F1151',(#1409),#1403,.T.);
#1411=CARTESIAN_POINT('',(0.,0.,0.));
#1412=DIRECTION('',(0.,1.,0.));
#1413=DIRECTION('',(0.,0.,1.));
#1414=AXIS2_PLACEMENT_3D('',#1411,#1412,#1413);
#1415=PLANE('',#1414);
#1416=CARTESIAN_POINT('',(-57.15,0.,57.15));
#1417=DIRECTION('',(0.,1.,0.));
#1418=DIRECTION('',(0.,0.,1.));
#1419=AXIS2_PLACEMENT_3D('',#1416,#1417,#1418);
#1420=CIRCLE('',#1419,2.24789999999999);
#1421=CARTESIAN_POINT('',(-57.15,0.,59.3979));
#1422=VERTEX_POINT('',#1421);
#1423=EDGE_CURVE('E995',#1422,#1422,#1420,.T.);
#1424=ORIENTED_EDGE('',*,*,#1423,.T.);
#1425=EDGE_LOOP('',(#1424));
#1426=FACE_BOUND('',#1425,.T.);
#1427=CARTESIAN_POINT('',(57.1500000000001,0.,57.15));
#1428=DIRECTION('',(0.,1.,0.));
#1429=DIRECTION('',(0.,0.,1.));
#1430=AXIS2_PLACEMENT_3D('',#1427,#1428,#1429);
#1431=CIRCLE('',#1430,2.24789999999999);
#1432=CARTESIAN_POINT('',(57.1500000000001,0.,59.3979));
#1433=VERTEX_POINT('',#1432);
#1434=EDGE_CURVE('E1063',#1433,#1433,#1431,.T.);
#1435=ORIENTED_EDGE('',*,*,#1434,.T.);
#1436=EDGE_LOOP('',(#1435));
#1437=FACE_BOUND('',#1436,.T.);
#1438=ORIENTED_EDGE('',*,*,#1200,.F.);
#1439=ORIENTED_EDGE('',*,*,#1386,.F.);
#1440=ORIENTED_EDGE('',*,*,#1313,.F.);
#1441=ORIENTED_EDGE('',*,*,#1282,.F.);
#1442=EDGE_LOOP('',(#1438,#1439,#1440,#1441));
#1443=FACE_BOUND('',#1442,.T.);
#1444=ADVANCED_FACE('F1120',(#1426,#1437,#1443),#1415,.F.);
#1445=CARTESIAN_POINT('',(107.95,33.8666666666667,63.5));
#1446=DIRECTION('',(0.,0.,1.));
#1447=DIRECTION('',(1.,0.,0.));
#1448=AXIS2_PLACEMENT_3D('',#1445,#1446,#1447);
#1449=CYLINDRICAL_SURFACE('',#1448,2.2479);
#1450=CARTESIAN_POINT('',(107.95,33.8666666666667,61.8482323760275));
#1451=DIRECTION('',(0.,0.,1.));
#1452=DIRECTION('',(1.,0.,0.));
#1453=AXIS2_PLACEMENT_3D('',#1450,#1451,#1452);
#1454=CIRCLE('',#1453,2.2479);
#1455=CARTESIAN_POINT('',(110.1979,33.8666666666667,61.8482323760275));
#1456=VERTEX_POINT('',#1455);
#1457=EDGE_CURVE('E1088',#1456,#1456,#1454,.T.);
#1458=ORIENTED_EDGE('',*,*,#1457,.T.);
#1459=EDGE_LOOP('',(#1458));
#1460=FACE_BOUND('',#1459,.T.);
#1461=ORIENTED_EDGE('',*,*,#1378,.F.);
#1462=EDGE_LOOP('',(#1461));
#1463=FACE_BOUND('',#1462,.T.);
#1464=ADVANCED_FACE('F1159',(#1460,#1463),#1449,.F.);
#1465=CARTESIAN_POINT('',(107.95,33.8666666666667,63.5));
#1466=DIRECTION('',(0.,0.,1.));
#1467=DIRECTION('',(1.,0.,0.));
#1468=AXIS2_PLACEMENT_3D('',#1465,#1466,#1467);
#1469=CONICAL_SURFACE('',#1468,4.21639999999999,0.872664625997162);
#1470=ORIENTED_EDGE('',*,*,#1457,.F.);
#1471=EDGE_LOOP('',(#1470));
#1472=FACE_BOUND('',#1471,.T.);
#1473=ORIENTED_EDGE('',*,*,#1272,.T.);
#1474=EDGE_LOOP('',(#1473));
#1475=FACE_BOUND('',#1474,.T.);
#1476=ADVANCED_FACE('F1188',(#1472,#1475),#1469,.F.);
#1477=CARTESIAN_POINT('',(107.95,67.7333333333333,63.5));
#1478=DIRECTION('',(0.,0.,1.));
#1479=DIRECTION('',(1.,0.,0.));
#1480=AXIS2_PLACEMENT_3D('',#1477,#1478,#1479);
#1481=CYLINDRICAL_SURFACE('',#1480,2.2479);
#1482=CARTESIAN_POINT('',(107.95,67.7333333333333,61.8482323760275));
#1483=DIRECTION('',(0.,0.,1.));
#1484=DIRECTION('',(1.,0.,0.));
#1485=AXIS2_PLACEMENT_3D('',#1482,#1483,#1484);
#1486=CIRCLE('',#1485,2.2479);
#1487=CARTESIAN_POINT('',(110.1979,67.7333333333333,61.8482323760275));
#1488=VERTEX_POINT('',#1487);
#1489=EDGE_CURVE('E1081',#1488,#1488,#1486,.T.);
#1490=ORIENTED_EDGE('',*,*,#1489,.T.);
#1491=EDGE_LOOP('',(#1490));
#1492=FACE_BOUND('',#1491,.T.);
#1493=ORIENTED_EDGE('',*,*,#1367,.F.);
#1494=EDGE_LOOP('',(#1493));
#1495=FACE_BOUND('',#1494,.T.);
#1496=ADVANCED_FACE('F1198',(#1492,#1495),#1481,.F.);
#1497=CARTESIAN_POINT('',(107.95,67.7333333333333,63.5));
#1498=DIRECTION('',(0.,0.,1.));
#1499=DIRECTION('',(1.,0.,0.));
#1500=AXIS2_PLACEMENT_3D('',#1497,#1498,#1499);
#1501=CONICAL_SURFACE('',#1500,4.21639999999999,0.872664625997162);
#1502=ORIENTED_EDGE('',*,*,#1489,.F.);
#1503=EDGE_LOOP('',(#1502));
#1504=FACE_BOUND('',#1503,.T.);
#1505=ORIENTED_EDGE('',*,*,#1261,.T.);
#1506=EDGE_LOOP('',(#1505));
#1507=FACE_BOUND('',#1506,.T.);
#1508=ADVANCED_FACE('F1207',(#1504,#1507),#1501,.F.);
#1509=CARTESIAN_POINT('',(-107.95,33.8666666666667,63.5));
#1510=DIRECTION('',(0.,0.,1.));
#1511=DIRECTION('',(1.,0.,0.));
#1512=AXIS2_PLACEMENT_3D('',#1509,#1510,#1511);
#1513=CYLINDRICAL_SURFACE('',#1512,2.2479);
#1514=CARTESIAN_POINT('',(-107.95,33.8666666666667,61.8482323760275));
#1515=DIRECTION('',(0.,0.,1.));
#1516=DIRECTION('',(1.,0.,0.));
#1517=AXIS2_PLACEMENT_3D('',#1514,#1515,#1516);
#1518=CIRCLE('',#1517,2.2479);
#1519=CARTESIAN_POINT('',(-105.7021,33.8666666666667,61.8482323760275));
#1520=VERTEX_POINT('',#1519);
#1521=EDGE_CURVE('E1074',#1520,#1520,#1518,.T.);
#1522=ORIENTED_EDGE('',*,*,#1521,.T.);
#1523=EDGE_LOOP('',(#1522));
#1524=FACE_BOUND('',#1523,.T.);
#1525=ORIENTED_EDGE('',*,*,#1356,.F.);
#1526=EDGE_LOOP('',(#1525));
#1527=FACE_BOUND('',#1526,.T.);
#1528=ADVANCED_FACE('F1217',(#1524,#1527),#1513,.F.);
#1529=CARTESIAN_POINT('',(-107.95,33.8666666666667,63.5));
#1530=DIRECTION('',(0.,0.,1.));
#1531=DIRECTION('',(1.,0.,0.));
#1532=AXIS2_PLACEMENT_3D('',#1529,#1530,#1531);
#1533=CONICAL_SURFACE('',#1532,4.21639999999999,0.872664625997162);
#1534=ORIENTED_EDGE('',*,*,#1521,.F.);
#1535=EDGE_LOOP('',(#1534));
#1536=FACE_BOUND('',#1535,.T.);
#1537=ORIENTED_EDGE('',*,*,#1250,.T.);
#1538=EDGE_LOOP('',(#1537));
#1539=FACE_BOUND('',#1538,.T.);
#1540=ADVANCED_FACE('F1227',(#1536,#1539),#1533,.F.);
#1541=CARTESIAN_POINT('',(-107.95,67.7333333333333,63.5));
#1542=DIRECTION('',(0.,0.,1.));
#1543=DIRECTION('',(1.,0.,0.));
#1544=AXIS2_PLACEMENT_3D('',#1541,#1542,#1543);
#1545=CYLINDRICAL_SURFACE('',#1544,2.2479);
#1546=CARTESIAN_POINT('',(-107.95,67.7333333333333,61.8482323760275));
#1547=DIRECTION('',(0.,0.,1.));
#1548=DIRECTION('',(1.,0.,0.));
#1549=AXIS2_PLACEMENT_3D('',#1546,#1547,#1548);
#1550=CIRCLE('',#1549,2.2479);
#1551=CARTESIAN_POINT('',(-105.7021,67.7333333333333,61.8482323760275));
#1552=VERTEX_POINT('',#1551);
#1553=EDGE_CURVE('E1067',#1552,#1552,#1550,.T.);
#1554=ORIENTED_EDGE('',*,*,#1553,.T.);
#1555=EDGE_LOOP('',(#1554));
#1556=FACE_BOUND('',#1555,.T.);
#1557=ORIENTED_EDGE('',*,*,#1345,.F.);
#1558=EDGE_LOOP('',(#1557));
#1559=FACE_BOUND('',#1558,.T.);
#1560=ADVANCED_FACE('F1135',(#1556,#1559),#1545,.F.);
#1561=CARTESIAN_POINT('',(-107.95,67.7333333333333,63.5));
#1562=DIRECTION('',(0.,0.,1.));
#1563=DIRECTION('',(1.,0.,0.));
#1564=AXIS2_PLACEMENT_3D('',#1561,#1562,#1563);
#1565=CONICAL_SURFACE('',#1564,4.21639999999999,0.872664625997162);
#1566=ORIENTED_EDGE('',*,*,#1553,.F.);
#1567=EDGE_LOOP('',(#1566));
#1568=FACE_BOUND('',#1567,.T.);
#1569=ORIENTED_EDGE('',*,*,#1239,.T.);
#1570=EDGE_LOOP('',(#1569));
#1571=FACE_BOUND('',#1570,.T.);
#1572=ADVANCED_FACE('F1126',(#1568,#1571),#1565,.F.);
#1573=CARTESIAN_POINT('',(57.1500000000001,-12.7,57.15));
#1574=DIRECTION('',(0.,-1.,0.));
#1575=DIRECTION('',(0.,0.,-1.));
#1576=AXIS2_PLACEMENT_3D('',#1573,#1574,#1575);
#1577=CYLINDRICAL_SURFACE('',#1576,2.24789999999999);
#1578=CARTESIAN_POINT('',(57.1500000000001,17.272,57.15));
#1579=DIRECTION('',(0.,-1.,0.));
#1580=DIRECTION('',(0.,0.,-1.));
#1581=AXIS2_PLACEMENT_3D('',#1578,#1579,#1580);
#1582=CIRCLE('',#1581,2.24789999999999);
#1583=CARTESIAN_POINT('',(57.1500000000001,17.272,54.9021));
#1584=VERTEX_POINT('',#1583);
#1585=EDGE_CURVE('E1059',#1584,#1584,#1582,.T.);
#1586=ORIENTED_EDGE('',*,*,#1585,.F.);
#1587=EDGE_LOOP('',(#1586));
#1588=FACE_BOUND('',#1587,.T.);
#1589=ORIENTED_EDGE('',*,*,#1434,.F.);
#1590=EDGE_LOOP('',(#1589));
#1591=FACE_BOUND('',#1590,.T.);
#1592=ADVANCED_FACE('F1123',(#1588,#1591),#1577,.F.);
#1593=CARTESIAN_POINT('',(57.1500000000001,17.272,57.15));
#1594=DIRECTION('',(0.,-1.,0.));
#1595=DIRECTION('',(0.,0.,-1.));
#1596=AXIS2_PLACEMENT_3D('',#1593,#1594,#1595);
#1597=CONICAL_SURFACE('',#1596,2.24789999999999,1.02974425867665);
#1598=CARTESIAN_POINT('',(57.15,18.6226745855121,57.15));
#1599=VERTEX_POINT('',#1598);
#1600=VERTEX_LOOP('',#1599);
#1601=FACE_BOUND('',#1600,.T.);
#1602=ORIENTED_EDGE('',*,*,#1585,.T.);
#1603=EDGE_LOOP('',(#1602));
#1604=FACE_BOUND('',#1603,.T.);
#1605=ADVANCED_FACE('F1125',(#1601,#1604),#1597,.F.);
#1606=CARTESIAN_POINT('',(-57.15,-12.7,57.15));
#1607=DIRECTION('',(0.,-1.,0.));
#1608=DIRECTION('',(0.,0.,-1.));
#1609=AXIS2_PLACEMENT_3D('',#1606,#1607,#1608);
#1610=CYLINDRICAL_SURFACE('',#1609,2.24789999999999);
#1611=CARTESIAN_POINT('',(-57.15,17.272,57.15));
#1612=DIRECTION('',(0.,-1.,0.));
#1613=DIRECTION('',(0.,0.,-1.));
#1614=AXIS2_PLACEMENT_3D('',#1611,#1612,#1613);
#1615=CIRCLE('',#1614,2.24789999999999);
#1616=CARTESIAN_POINT('',(-57.15,17.272,54.9021));
#1617=VERTEX_POINT('',#1616);
#1618=EDGE_CURVE('E1055',#1617,#1617,#1615,.T.);
#1619=ORIENTED_EDGE('',*,*,#1618,.F.);
#1620=EDGE_LOOP('',(#1619));
#1621=FACE_BOUND('',#1620,.T.);
#1622=ORIENTED_EDGE('',*,*,#1423,.F.);
#1623=EDGE_LOOP('',(#1622));
#1624=FACE_BOUND('',#1623,.T.);
#1625=ADVANCED_FACE('F1051',(#1621,#1624),#1610,.F.);
#1626=CARTESIAN_POINT('',(-57.15,17.272,57.15));
#1627=DIRECTION('',(0.,-1.,0.));
#1628=DIRECTION('',(0.,0.,-1.));
#1629=AXIS2_PLACEMENT_3D('',#1626,#1627,#1628);
#1630=CONICAL_SURFACE('',#1629,2.24789999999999,1.02974425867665);
#1631=CARTESIAN_POINT('',(-57.15,18.6226745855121,57.15));
#1632=VERTEX_POINT('',#1631);
#1633=VERTEX_LOOP('',#1632);
#1634=FACE_BOUND('',#1633,.T.);
#1635=ORIENTED_EDGE('',*,*,#1618,.T.);
#1636=EDGE_LOOP('',(#1635));
#1637=FACE_BOUND('',#1636,.T.);
#1638=ADVANCED_FACE('F1048',(#1634,#1637),#1630,.F.);
#1639=CLOSED_SHELL('',(#1226,#1301,#1332,#1398,#1410,#1444,#1464,#1476,#1496,#1508,#1528,#1540,
#1560,#1572,#1592,#1605,#1625,#1638));
#1640=MANIFOLD_SOLID_BREP('B447',#1639);
#1641=CARTESIAN_POINT('',(-114.3,101.6,-50.8));
#1642=DIRECTION('',(1.,0.,0.));
#1643=DIRECTION('',(0.,0.,-1.));
#1644=AXIS2_PLACEMENT_3D('',#1641,#1642,#1643);
#1645=PLANE('',#1644);
#1646=DIRECTION('',(0.,0.,1.));
#1647=VECTOR('',#1646,1.);
#1648=CARTESIAN_POINT('',(-114.3,0.,-50.8));
#1649=LINE('',#1648,#1647);
#1650=CARTESIAN_POINT('',(-114.3,0.,-63.5));
#1651=VERTEX_POINT('',#1650);
#1652=CARTESIAN_POINT('',(-114.3,0.,-50.8));
#1653=VERTEX_POINT('',#1652);
#1654=EDGE_CURVE('E1436',#1651,#1653,#1649,.T.);
#1655=ORIENTED_EDGE('',*,*,#1654,.T.);
#1656=DIRECTION('',(0.,-1.,0.));
#1657=VECTOR('',#1656,1.);
#1658=CARTESIAN_POINT('',(-114.3,101.6,-50.8));
#1659=LINE('',#1658,#1657);
#1660=CARTESIAN_POINT('',(-114.3,101.6,-50.8));
#1661=VERTEX_POINT('',#1660);
#1662=EDGE_CURVE('E990',#1661,#1653,#1659,.T.);
#1663=ORIENTED_EDGE('',*,*,#1662,.F.);
#1664=DIRECTION('',(0.,0.,1.));
#1665=VECTOR('',#1664,1.);
#1666=CARTESIAN_POINT('',(-114.3,101.6,-50.8));
#1667=LINE('',#1666,#1665);
#1668=CARTESIAN_POINT('',(-114.3,101.6,-63.5));
#1669=VERTEX_POINT('',#1668);
#1670=EDGE_CURVE('E1437',#1669,#1661,#1667,.T.);
#1671=ORIENTED_EDGE('',*,*,#1670,.F.);
#1672=DIRECTION('',(0.,-1.,0.));
#1673=VECTOR('',#1672,1.);
#1674=CARTESIAN_POINT('',(-114.3,101.6,-63.5));
#1675=LINE('',#1674,#1673);
#1676=EDGE_CURVE('E1443',#1669,#1651,#1675,.T.);
#1677=ORIENTED_EDGE('',*,*,#1676,.T.);
#1678=EDGE_LOOP('',(#1655,#1663,#1671,#1677));
#1679=FACE_BOUND('',#1678,.T.);
#1680=ADVANCED_FACE('F1327',(#1679),#1645,.F.);
#1681=CARTESIAN_POINT('',(114.3,101.6,-50.8));
#1682=DIRECTION('',(0.,0.,-1.));
#1683=DIRECTION('',(-1.,0.,0.));
#1684=AXIS2_PLACEMENT_3D('',#1681,#1682,#1683);
#1685=PLANE('',#1684);
#1686=CARTESIAN_POINT('',(-107.95,33.8666666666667,-50.8));
#1687=DIRECTION('',(0.,0.,1.));
#1688=DIRECTION('',(1.,0.,0.));
#1689=AXIS2_PLACEMENT_3D('',#1686,#1687,#1688);
#1690=CIRCLE('',#1689,2.2479);
#1691=CARTESIAN_POINT('',(-105.7021,33.8666666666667,-50.8));
#1692=VERTEX_POINT('',#1691);
#1693=EDGE_CURVE('E1403',#1692,#1692,#1690,.T.);
#1694=ORIENTED_EDGE('',*,*,#1693,.F.);
#1695=EDGE_LOOP('',(#1694));
#1696=FACE_BOUND('',#1695,.T.);
#1697=CARTESIAN_POINT('',(107.95,67.7333333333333,-50.8));
#1698=DIRECTION('',(0.,0.,1.));
#1699=DIRECTION('',(1.,0.,0.));
#1700=AXIS2_PLACEMENT_3D('',#1697,#1698,#1699);
#1701=CIRCLE('',#1700,2.2479);
#1702=CARTESIAN_POINT('',(110.1979,67.7333333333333,-50.8));
#1703=VERTEX_POINT('',#1702);
#1704=EDGE_CURVE('E1412',#1703,#1703,#1701,.T.);
#1705=ORIENTED_EDGE('',*,*,#1704,.F.);
#1706=EDGE_LOOP('',(#1705));
#1707=FACE_BOUND('',#1706,.T.);
#1708=CARTESIAN_POINT('',(107.95,33.8666666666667,-50.8));
#1709=DIRECTION('',(0.,0.,1.));
#1710=DIRECTION('',(1.,0.,0.));
#1711=AXIS2_PLACEMENT_3D('',#1708,#1709,#1710);
#1712=CIRCLE('',#1711,2.2479);
#1713=CARTESIAN_POINT('',(110.1979,33.8666666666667,-50.8));
#1714=VERTEX_POINT('',#1713);
#1715=EDGE_CURVE('E1421',#1714,#1714,#1712,.T.);
#1716=ORIENTED_EDGE('',*,*,#1715,.F.);
#1717=EDGE_LOOP('',(#1716));
#1718=FACE_BOUND('',#1717,.T.);
#1719=CARTESIAN_POINT('',(-107.95,67.7333333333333,-50.8));
#1720=DIRECTION('',(0.,0.,1.));
#1721=DIRECTION('',(1.,0.,0.));
#1722=AXIS2_PLACEMENT_3D('',#1719,#1720,#1721);
#1723=CIRCLE('',#1722,2.2479);
#1724=CARTESIAN_POINT('',(-105.7021,67.7333333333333,-50.8));
#1725=VERTEX_POINT('',#1724);
#1726=EDGE_CURVE('E1430',#1725,#1725,#1723,.T.);
#1727=ORIENTED_EDGE('',*,*,#1726,.F.);
#1728=EDGE_LOOP('',(#1727));
#1729=FACE_BOUND('',#1728,.T.);
#1730=DIRECTION('',(1.,0.,0.));
#1731=VECTOR('',#1730,1.);
#1732=CARTESIAN_POINT('',(114.3,0.,-50.8));
#1733=LINE('',#1732,#1731);
#1734=CARTESIAN_POINT('',(114.3,0.,-50.8));
#1735=VERTEX_POINT('',#1734);
#1736=EDGE_CURVE('E1446',#1653,#1735,#1733,.T.);
#1737=ORIENTED_EDGE('',*,*,#1736,.T.);
#1738=DIRECTION('',(0.,-1.,0.));
#1739=VECTOR('',#1738,1.);
#1740=CARTESIAN_POINT('',(114.3,101.6,-50.8));
#1741=LINE('',#1740,#1739);
#1742=CARTESIAN_POINT('',(114.3,101.6,-50.8));
#1743=VERTEX_POINT('',#1742);
#1744=EDGE_CURVE('E1336',#1743,#1735,#1741,.T.);
#1745=ORIENTED_EDGE('',*,*,#1744,.F.);
#1746=DIRECTION('',(1.,0.,0.));
#1747=VECTOR('',#1746,1.);
#1748=CARTESIAN_POINT('',(114.3,101.6,-50.8));
#1749=LINE('',#1748,#1747);
#1750=EDGE_CURVE('E1376',#1661,#1743,#1749,.T.);
#1751=ORIENTED_EDGE('',*,*,#1750,.F.);
#1752=ORIENTED_EDGE('',*,*,#1662,.T.);
#1753=EDGE_LOOP('',(#1737,#1745,#1751,#1752));
#1754=FACE_BOUND('',#1753,.T.);
#1755=ADVANCED_FACE('F1472',(#1696,#1707,#1718,#1729,#1754),#1685,.F.);
#1756=CARTESIAN_POINT('',(114.3,101.6,-63.5));
#1757=DIRECTION('',(-1.,0.,0.));
#1758=DIRECTION('',(0.,0.,1.));
#1759=AXIS2_PLACEMENT_3D('',#1756,#1757,#1758);
#1760=PLANE('',#1759);
#1761=DIRECTION('',(0.,0.,-1.));
#1762=VECTOR('',#1761,1.);
#1763=CARTESIAN_POINT('',(114.3,0.,-63.5));
#1764=LINE('',#1763,#1762);
#1765=CARTESIAN_POINT('',(114.3,0.,-63.5));
#1766=VERTEX_POINT('',#1765);
#1767=EDGE_CURVE('E1363',#1735,#1766,#1764,.T.);
#1768=ORIENTED_EDGE('',*,*,#1767,.T.);
#1769=DIRECTION('',(0.,-1.,0.));
#1770=VECTOR('',#1769,1.);
#1771=CARTESIAN_POINT('',(114.3,101.6,-63.5));
#1772=LINE('',#1771,#1770);
#1773=CARTESIAN_POINT('',(114.3,101.6,-63.5));
#1774=VERTEX_POINT('',#1773);
#1775=EDGE_CURVE('E1451',#1774,#1766,#1772,.T.);
#1776=ORIENTED_EDGE('',*,*,#1775,.F.);
#1777=DIRECTION('',(0.,0.,-1.));
#1778=VECTOR('',#1777,1.);
#1779=CARTESIAN_POINT('',(114.3,101.6,-63.5));
#1780=LINE('',#1779,#1778);
#1781=EDGE_CURVE('E1440',#1743,#1774,#1780,.T.);
#1782=ORIENTED_EDGE('',*,*,#1781,.F.);
#1783=ORIENTED_EDGE('',*,*,#1744,.T.);
#1784=EDGE_LOOP('',(#1768,#1776,#1782,#1783));
#1785=FACE_BOUND('',#1784,.T.);
#1786=ADVANCED_FACE('F1471',(#1785),#1760,.F.);
#1787=CARTESIAN_POINT('',(-114.3,101.6,-63.5));
#1788=DIRECTION('',(0.,0.,1.));
#1789=DIRECTION('',(1.,0.,0.));
#1790=AXIS2_PLACEMENT_3D('',#1787,#1788,#1789);
#1791=PLANE('',#1790);
#1792=CARTESIAN_POINT('',(-107.95,33.8666666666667,-63.5));
#1793=DIRECTION('',(0.,0.,1.));
#1794=DIRECTION('',(1.,0.,0.));
#1795=AXIS2_PLACEMENT_3D('',#1792,#1793,#1794);
#1796=CIRCLE('',#1795,4.21639999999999);
#1797=CARTESIAN_POINT('',(-103.7336,33.8666666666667,-63.5));
#1798=VERTEX_POINT('',#1797);
#1799=EDGE_CURVE('E1400',#1798,#1798,#1796,.T.);
#1800=ORIENTED_EDGE('',*,*,#1799,.T.);
#1801=EDGE_LOOP('',(#1800));
#1802=FACE_BOUND('',#1801,.T.);
#1803=CARTESIAN_POINT('',(107.95,67.7333333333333,-63.5));
#1804=DIRECTION('',(0.,0.,1.));
#1805=DIRECTION('',(1.,0.,0.));
#1806=AXIS2_PLACEMENT_3D('',#1803,#1804,#1805);
#1807=CIRCLE('',#1806,4.21639999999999);
#1808=CARTESIAN_POINT('',(112.1664,67.7333333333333,-63.5));
#1809=VERTEX_POINT('',#1808);
#1810=EDGE_CURVE('E1409',#1809,#1809,#1807,.T.);
#1811=ORIENTED_EDGE('',*,*,#1810,.T.);
#1812=EDGE_LOOP('',(#1811));
#1813=FACE_BOUND('',#1812,.T.);
#1814=CARTESIAN_POINT('',(107.95,33.8666666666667,-63.5));
#1815=DIRECTION('',(0.,0.,1.));
#1816=DIRECTION('',(1.,0.,0.));
#1817=AXIS2_PLACEMENT_3D('',#1814,#1815,#1816);
#1818=CIRCLE('',#1817,4.21639999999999);
#1819=CARTESIAN_POINT('',(112.1664,33.8666666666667,-63.5));
#1820=VERTEX_POINT('',#1819);
#1821=EDGE_CURVE('E1418',#1820,#1820,#1818,.T.);
#1822=ORIENTED_EDGE('',*,*,#1821,.T.);
#1823=EDGE_LOOP('',(#1822));
#1824=FACE_BOUND('',#1823,.T.);
#1825=CARTESIAN_POINT('',(-107.95,67.7333333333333,-63.5));
#1826=DIRECTION('',(0.,0.,1.));
#1827=DIRECTION('',(1.,0.,0.));
#1828=AXIS2_PLACEMENT_3D('',#1825,#1826,#1827);
#1829=CIRCLE('',#1828,4.21639999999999);
#1830=CARTESIAN_POINT('',(-103.7336,67.7333333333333,-63.5));
#1831=VERTEX_POINT('',#1830);
#1832=EDGE_CURVE('E1427',#1831,#1831,#1829,.T.);
#1833=ORIENTED_EDGE('',*,*,#1832,.T.);
#1834=EDGE_LOOP('',(#1833));
#1835=FACE_BOUND('',#1834,.T.);
#1836=DIRECTION('',(-1.,0.,0.));
#1837=VECTOR('',#1836,1.);
#1838=CARTESIAN_POINT('',(-114.3,0.,-63.5));
#1839=LINE('',#1838,#1837);
#1840=EDGE_CURVE('E1369',#1766,#1651,#1839,.T.);
#1841=ORIENTED_EDGE('',*,*,#1840,.T.);
#1842=ORIENTED_EDGE('',*,*,#1676,.F.);
#1843=DIRECTION('',(-1.,0.,0.));
#1844=VECTOR('',#1843,1.);
#1845=CARTESIAN_POINT('',(-114.3,101.6,-63.5));
#1846=LINE('',#1845,#1844);
#1847=EDGE_CURVE('E1345',#1774,#1669,#1846,.T.);
#1848=ORIENTED_EDGE('',*,*,#1847,.F.);
#1849=ORIENTED_EDGE('',*,*,#1775,.T.);
#1850=EDGE_LOOP('',(#1841,#1842,#1848,#1849));
#1851=FACE_BOUND('',#1850,.T.);
#1852=ADVANCED_FACE('F1469',(#1802,#1813,#1824,#1835,#1851),#1791,.F.);
#1853=CARTESIAN_POINT('',(0.,101.6,0.));
#1854=DIRECTION('',(0.,-1.,0.));
#1855=DIRECTION('',(0.,0.,-1.));
#1856=AXIS2_PLACEMENT_3D('',#1853,#1854,#1855);
#1857=PLANE('',#1856);
#1858=ORIENTED_EDGE('',*,*,#1670,.T.);
#1859=ORIENTED_EDGE('',*,*,#1750,.T.);
#1860=ORIENTED_EDGE('',*,*,#1781,.T.);
#1861=ORIENTED_EDGE('',*,*,#1847,.T.);
#1862=EDGE_LOOP('',(#1858,#1859,#1860,#1861));
#1863=FACE_BOUND('',#1862,.T.);
#1864=ADVANCED_FACE('F1462',(#1863),#1857,.F.);
#1865=CARTESIAN_POINT('',(0.,0.,0.));
#1866=DIRECTION('',(0.,-1.,0.));
#1867=DIRECTION('',(0.,0.,-1.));
#1868=AXIS2_PLACEMENT_3D('',#1865,#1866,#1867);
#1869=PLANE('',#1868);
#1870=CARTESIAN_POINT('',(57.1500000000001,0.,-57.15));
#1871=DIRECTION('',(0.,-1.,0.));
#1872=DIRECTION('',(0.,0.,-1.));
#1873=AXIS2_PLACEMENT_3D('',#1870,#1871,#1872);
#1874=CIRCLE('',#1873,2.24789999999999);
#1875=CARTESIAN_POINT('',(57.1500000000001,0.,-59.3979));
#1876=VERTEX_POINT('',#1875);
#1877=EDGE_CURVE('E1330',#1876,#1876,#1874,.T.);
#1878=ORIENTED_EDGE('',*,*,#1877,.F.);
#1879=EDGE_LOOP('',(#1878));
#1880=FACE_BOUND('',#1879,.T.);
#1881=CARTESIAN_POINT('',(-57.15,0.,-57.15));
#1882=DIRECTION('',(0.,-1.,0.));
#1883=DIRECTION('',(0.,0.,-1.));
#1884=AXIS2_PLACEMENT_3D('',#1881,#1882,#1883);
#1885=CIRCLE('',#1884,2.24789999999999);
#1886=CARTESIAN_POINT('',(-57.15,0.,-59.3979));
#1887=VERTEX_POINT('',#1886);
#1888=EDGE_CURVE('E1399',#1887,#1887,#1885,.T.);
#1889=ORIENTED_EDGE('',*,*,#1888,.F.);
#1890=EDGE_LOOP('',(#1889));
#1891=FACE_BOUND('',#1890,.T.);
#1892=ORIENTED_EDGE('',*,*,#1654,.F.);
#1893=ORIENTED_EDGE('',*,*,#1840,.F.);
#1894=ORIENTED_EDGE('',*,*,#1767,.F.);
#1895=ORIENTED_EDGE('',*,*,#1736,.F.);
#1896=EDGE_LOOP('',(#1892,#1893,#1894,#1895));
#1897=FACE_BOUND('',#1896,.T.);
#1898=ADVANCED_FACE('F1458',(#1880,#1891,#1897),#1869,.T.);
#1899=CARTESIAN_POINT('',(-107.95,67.7333333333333,-63.5));
#1900=DIRECTION('',(0.,0.,-1.));
#1901=DIRECTION('',(1.,0.,0.));
#1902=AXIS2_PLACEMENT_3D('',#1899,#1900,#1901);
#1903=CYLINDRICAL_SURFACE('',#1902,2.2479);
#1904=CARTESIAN_POINT('',(-107.95,67.7333333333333,-61.8482323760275));
#1905=DIRECTION('',(0.,0.,1.));
#1906=DIRECTION('',(1.,0.,0.));
#1907=AXIS2_PLACEMENT_3D('',#1904,#1905,#1906);
#1908=CIRCLE('',#1907,2.2479);
#1909=CARTESIAN_POINT('',(-105.7021,67.7333333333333,-61.8482323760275));
#1910=VERTEX_POINT('',#1909);
#1911=EDGE_CURVE('E1433',#1910,#1910,#1908,.T.);
#1912=ORIENTED_EDGE('',*,*,#1911,.F.);
#1913=EDGE_LOOP('',(#1912));
#1914=FACE_BOUND('',#1913,.T.);
#1915=ORIENTED_EDGE('',*,*,#1726,.T.);
#1916=EDGE_LOOP('',(#1915));
#1917=FACE_BOUND('',#1916,.T.);
#1918=ADVANCED_FACE('F1461',(#1914,#1917),#1903,.F.);
#1919=CARTESIAN_POINT('',(-107.95,67.7333333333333,-63.5));
#1920=DIRECTION('',(0.,0.,-1.));
#1921=DIRECTION('',(1.,0.,0.));
#1922=AXIS2_PLACEMENT_3D('',#1919,#1920,#1921);
#1923=CONICAL_SURFACE('',#1922,4.21639999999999,0.872664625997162);
#1924=ORIENTED_EDGE('',*,*,#1911,.T.);
#1925=EDGE_LOOP('',(#1924));
#1926=FACE_BOUND('',#1925,.T.);
#1927=ORIENTED_EDGE('',*,*,#1832,.F.);
#1928=EDGE_LOOP('',(#1927));
#1929=FACE_BOUND('',#1928,.T.);
#1930=ADVANCED_FACE('F1490',(#1926,#1929),#1923,.F.);
#1931=CARTESIAN_POINT('',(107.95,33.8666666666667,-63.5));
#1932=DIRECTION('',(0.,0.,-1.));
#1933=DIRECTION('',(1.,0.,0.));
#1934=AXIS2_PLACEMENT_3D('',#1931,#1932,#1933);
#1935=CYLINDRICAL_SURFACE('',#1934,2.2479);
#1936=CARTESIAN_POINT('',(107.95,33.8666666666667,-61.8482323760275));
#1937=DIRECTION('',(0.,0.,1.));
#1938=DIRECTION('',(1.,0.,0.));
#1939=AXIS2_PLACEMENT_3D('',#1936,#1937,#1938);
#1940=CIRCLE('',#1939,2.2479);
#1941=CARTESIAN_POINT('',(110.1979,33.8666666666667,-61.8482323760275));
#1942=VERTEX_POINT('',#1941);
#1943=EDGE_CURVE('E1424',#1942,#1942,#1940,.T.);
#1944=ORIENTED_EDGE('',*,*,#1943,.F.);
#1945=EDGE_LOOP('',(#1944));
#1946=FACE_BOUND('',#1945,.T.);
#1947=ORIENTED_EDGE('',*,*,#1715,.T.);
#1948=EDGE_LOOP('',(#1947));
#1949=FACE_BOUND('',#1948,.T.);
#1950=ADVANCED_FACE('F1494',(#1946,#1949),#1935,.F.);
#1951=CARTESIAN_POINT('',(107.95,33.8666666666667,-63.5));
#1952=DIRECTION('',(0.,0.,-1.));
#1953=DIRECTION('',(1.,0.,0.));
#1954=AXIS2_PLACEMENT_3D('',#1951,#1952,#1953);
#1955=CONICAL_SURFACE('',#1954,4.21639999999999,0.872664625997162);
#1956=ORIENTED_EDGE('',*,*,#1943,.T.);
#1957=EDGE_LOOP('',(#1956));
#1958=FACE_BOUND('',#1957,.T.);
#1959=ORIENTED_EDGE('',*,*,#1821,.F.);
#1960=EDGE_LOOP('',(#1959));
#1961=FACE_BOUND('',#1960,.T.);
#1962=ADVANCED_FACE('F1498',(#1958,#1961),#1955,.F.);
#1963=CARTESIAN_POINT('',(107.95,67.7333333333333,-63.5));
#1964=DIRECTION('',(0.,0.,-1.));
#1965=DIRECTION('',(1.,0.,0.));
#1966=AXIS2_PLACEMENT_3D('',#1963,#1964,#1965);
#1967=CYLINDRICAL_SURFACE('',#1966,2.2479);
#1968=CARTESIAN_POINT('',(107.95,67.7333333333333,-61.8482323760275));
#1969=DIRECTION('',(0.,0.,1.));
#1970=DIRECTION('',(1.,0.,0.));
#1971=AXIS2_PLACEMENT_3D('',#1968,#1969,#1970);
#1972=CIRCLE('',#1971,2.2479);
#1973=CARTESIAN_POINT('',(110.1979,67.7333333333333,-61.8482323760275));
#1974=VERTEX_POINT('',#1973);
#1975=EDGE_CURVE('E1415',#1974,#1974,#1972,.T.);
#1976=ORIENTED_EDGE('',*,*,#1975,.F.);
#1977=EDGE_LOOP('',(#1976));
#1978=FACE_BOUND('',#1977,.T.);
#1979=ORIENTED_EDGE('',*,*,#1704,.T.);
#1980=EDGE_LOOP('',(#1979));
#1981=FACE_BOUND('',#1980,.T.);
#1982=ADVANCED_FACE('F1502',(#1978,#1981),#1967,.F.);
#1983=CARTESIAN_POINT('',(107.95,67.7333333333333,-63.5));
#1984=DIRECTION('',(0.,0.,-1.));
#1985=DIRECTION('',(1.,0.,0.));
#1986=AXIS2_PLACEMENT_3D('',#1983,#1984,#1985);
#1987=CONICAL_SURFACE('',#1986,4.21639999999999,0.872664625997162);
#1988=ORIENTED_EDGE('',*,*,#1975,.T.);
#1989=EDGE_LOOP('',(#1988));
#1990=FACE_BOUND('',#1989,.T.);
#1991=ORIENTED_EDGE('',*,*,#1810,.F.);
#1992=EDGE_LOOP('',(#1991));
#1993=FACE_BOUND('',#1992,.T.);
#1994=ADVANCED_FACE('F1506',(#1990,#1993),#1987,.F.);
#1995=CARTESIAN_POINT('',(-107.95,33.8666666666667,-63.5));
#1996=DIRECTION('',(0.,0.,-1.));
#1997=DIRECTION('',(1.,0.,0.));
#1998=AXIS2_PLACEMENT_3D('',#1995,#1996,#1997);
#1999=CYLINDRICAL_SURFACE('',#1998,2.2479);
#2000=CARTESIAN_POINT('',(-107.95,33.8666666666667,-61.8482323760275));
#2001=DIRECTION('',(0.,0.,1.));
#2002=DIRECTION('',(1.,0.,0.));
#2003=AXIS2_PLACEMENT_3D('',#2000,#2001,#2002);
#2004=CIRCLE('',#2003,2.2479);
#2005=CARTESIAN_POINT('',(-105.7021,33.8666666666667,-61.8482323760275));
#2006=VERTEX_POINT('',#2005);
#2007=EDGE_CURVE('E1406',#2006,#2006,#2004,.T.);
#2008=ORIENTED_EDGE('',*,*,#2007,.F.);
#2009=EDGE_LOOP('',(#2008));
#2010=FACE_BOUND('',#2009,.T.);
#2011=ORIENTED_EDGE('',*,*,#1693,.T.);
#2012=EDGE_LOOP('',(#2011));
#2013=FACE_BOUND('',#2012,.T.);
#2014=ADVANCED_FACE('F1510',(#2010,#2013),#1999,.F.);
#2015=CARTESIAN_POINT('',(-107.95,33.8666666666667,-63.5));
#2016=DIRECTION('',(0.,0.,-1.));
#2017=DIRECTION('',(1.,0.,0.));
#2018=AXIS2_PLACEMENT_3D('',#2015,#2016,#2017);
#2019=CONICAL_SURFACE('',#2018,4.21639999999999,0.872664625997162);
#2020=ORIENTED_EDGE('',*,*,#2007,.T.);
#2021=EDGE_LOOP('',(#2020));
#2022=FACE_BOUND('',#2021,.T.);
#2023=ORIENTED_EDGE('',*,*,#1799,.F.);
#2024=EDGE_LOOP('',(#2023));
#2025=FACE_BOUND('',#2024,.T.);
#2026=ADVANCED_FACE('F1514',(#2022,#2025),#2019,.F.);
#2027=CARTESIAN_POINT('',(-57.15,17.272,-57.15));
#2028=DIRECTION('',(0.,-1.,0.));
#2029=DIRECTION('',(0.,0.,-1.));
#2030=AXIS2_PLACEMENT_3D('',#2027,#2028,#2029);
#2031=CONICAL_SURFACE('',#2030,2.24789999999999,1.02974425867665);
#2032=CARTESIAN_POINT('',(-57.15,18.6226745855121,-57.15));
#2033=VERTEX_POINT('',#2032);
#2034=VERTEX_LOOP('',#2033);
#2035=FACE_BOUND('',#2034,.T.);
#2036=CARTESIAN_POINT('',(-57.15,17.272,-57.15));
#2037=DIRECTION('',(0.,-1.,0.));
#2038=DIRECTION('',(0.,0.,-1.));
#2039=AXIS2_PLACEMENT_3D('',#2036,#2037,#2038);
#2040=CIRCLE('',#2039,2.24789999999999);
#2041=CARTESIAN_POINT('',(-57.15,17.272,-59.3979));
#2042=VERTEX_POINT('',#2041);
#2043=EDGE_CURVE('E1395',#2042,#2042,#2040,.T.);
#2044=ORIENTED_EDGE('',*,*,#2043,.T.);
#2045=EDGE_LOOP('',(#2044));
#2046=FACE_BOUND('',#2045,.T.);
#2047=ADVANCED_FACE('F1518',(#2035,#2046),#2031,.F.);
#2048=CARTESIAN_POINT('',(-57.15,-12.7,-57.15));
#2049=DIRECTION('',(0.,-1.,0.));
#2050=DIRECTION('',(0.,0.,-1.));
#2051=AXIS2_PLACEMENT_3D('',#2048,#2049,#2050);
#2052=CYLINDRICAL_SURFACE('',#2051,2.24789999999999);
#2053=ORIENTED_EDGE('',*,*,#1888,.T.);
#2054=EDGE_LOOP('',(#2053));
#2055=FACE_BOUND('',#2054,.T.);
#2056=ORIENTED_EDGE('',*,*,#2043,.F.);
#2057=EDGE_LOOP('',(#2056));
#2058=FACE_BOUND('',#2057,.T.);
#2059=ADVANCED_FACE('F1387',(#2055,#2058),#2052,.F.);
#2060=CARTESIAN_POINT('',(57.1500000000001,17.272,-57.15));
#2061=DIRECTION('',(0.,-1.,0.));
#2062=DIRECTION('',(0.,0.,-1.));
#2063=AXIS2_PLACEMENT_3D('',#2060,#2061,#2062);
#2064=CONICAL_SURFACE('',#2063,2.24789999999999,1.02974425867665);
#2065=CARTESIAN_POINT('',(57.15,18.6226745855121,-57.15));
#2066=VERTEX_POINT('',#2065);
#2067=VERTEX_LOOP('',#2066);
#2068=FACE_BOUND('',#2067,.T.);
#2069=CARTESIAN_POINT('',(57.1500000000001,17.272,-57.15));
#2070=DIRECTION('',(0.,-1.,0.));
#2071=DIRECTION('',(0.,0.,-1.));
#2072=AXIS2_PLACEMENT_3D('',#2069,#2070,#2071);
#2073=CIRCLE('',#2072,2.24789999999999);
#2074=CARTESIAN_POINT('',(57.1500000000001,17.272,-59.3979));
#2075=VERTEX_POINT('',#2074);
#2076=EDGE_CURVE('E1391',#2075,#2075,#2073,.T.);
#2077=ORIENTED_EDGE('',*,*,#2076,.T.);
#2078=EDGE_LOOP('',(#2077));
#2079=FACE_BOUND('',#2078,.T.);
#2080=ADVANCED_FACE('F1383',(#2068,#2079),#2064,.F.);
#2081=CARTESIAN_POINT('',(57.1500000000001,-12.7,-57.15));
#2082=DIRECTION('',(0.,-1.,0.));
#2083=DIRECTION('',(0.,0.,-1.));
#2084=AXIS2_PLACEMENT_3D('',#2081,#2082,#2083);
#2085=CYLINDRICAL_SURFACE('',#2084,2.24789999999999);
#2086=ORIENTED_EDGE('',*,*,#1877,.T.);
#2087=EDGE_LOOP('',(#2086));
#2088=FACE_BOUND('',#2087,.T.);
#2089=ORIENTED_EDGE('',*,*,#2076,.F.);
#2090=EDGE_LOOP('',(#2089));
#2091=FACE_BOUND('',#2090,.T.);
#2092=ADVANCED_FACE('F1386',(#2088,#2091),#2085,.F.);
#2093=CLOSED_SHELL('',(#1680,#1755,#1786,#1852,#1864,#1898,#1918,#1930,#1950,#1962,#1982,#1994,
#2014,#2026,#2047,#2059,#2080,#2092));
#2094=MANIFOLD_SOLID_BREP('B716',#2093);
#2095=ADVANCED_BREP_SHAPE_REPRESENTATION('',(#18,#168,#534,#860,#1186,#1640,#2094),#14);
#2096=SHAPE_DEFINITION_REPRESENTATION(#9,#2095);
ENDSEC;
END-ISO-10303-21;
